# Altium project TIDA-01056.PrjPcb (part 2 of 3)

## Sheet OPA625 ADC Driver_Power_1050.SchDoc
size 558 x 431 mm; Date: Not shown in title block; ApprovedBy: Not shown in title block; CheckedBy: Not shown in title block; Author: Not shown in title block; CompanyName: Not shown in title block; Engineer: Not shown in title block; Organization: Not shown in title block; Address1: Not shown in title block; Address2: Not shown in title block; Address3: Not shown in title block; Address4: Not shown in title block; DocumentNumber: 2; Revision: Use project parameter SCH_Rev; SheetNumber: 2; SheetTotal: 8; PageSetup: Record=PageOptions¦CenterHorizontal=True¦CenterVertical=True¦PrintScale=1.00¦XCorrection=1.00¦YCorrection=1.00¦PrintKind=0¦BorderSize=5000000¦LeftOffset=0¦BottomOffset=0¦Orientation=2¦PaperLength=1000¦PaperWidth=1000¦Scale=100¦PaperSource=15¦PrintQuality=600¦MediaType=1¦DitherType=10¦PaperKind=Letter¦PrintScaleMode=1

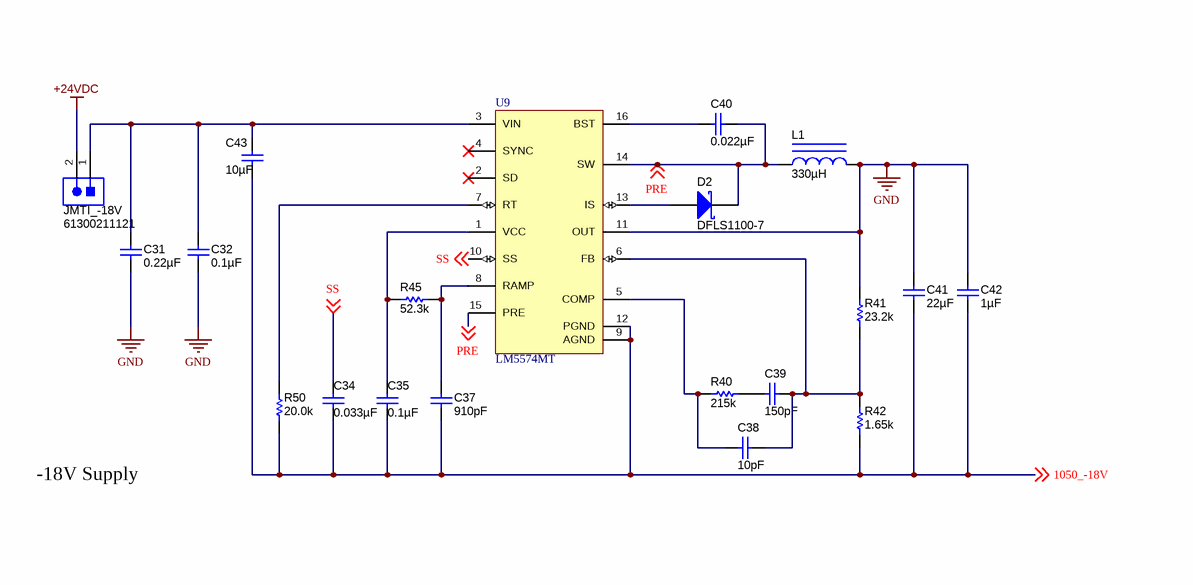
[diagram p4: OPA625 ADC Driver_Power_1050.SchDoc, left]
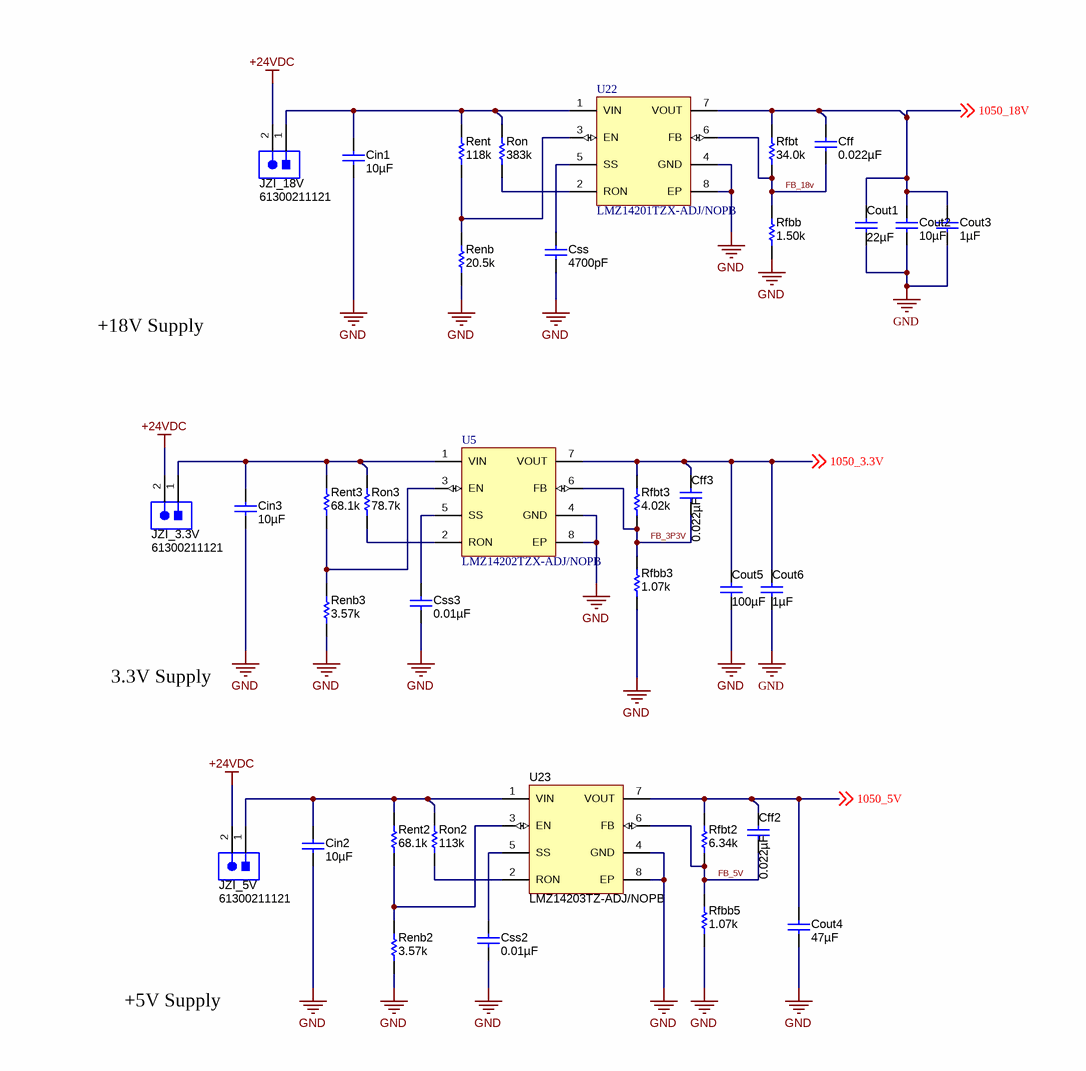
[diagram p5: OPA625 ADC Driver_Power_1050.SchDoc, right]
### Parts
C31  ValueDisplayed: 0.22µF  [0603]  (hidden comment: GCM188R71H224KA64D)
C32  ValueDisplayed: 0.1µF  [0603]  (hidden comment: C1608X7R1H104K080AA)
C34  ValueDisplayed: 0.033µF  [0603]  (hidden comment: GRM188R71H333KA61D)
C35  ValueDisplayed: 0.1µF  [0603]  (hidden comment: C1608X7R1H104K080AA)
C37  ValueDisplayed: 910pF  [0603]  (hidden comment: C0603C911J5GACTU)
C38  ValueDisplayed: 10pF  [0603]  (hidden comment: CGA3E2C0G1H100D080AA)
C39  ValueDisplayed: 150pF  [0603]  (hidden comment: GRM1885C1H151JA01D)
C40  ValueDisplayed: 0.022µF  [0603]  (hidden comment: GRM188R71H223KA01D)
C41  ValueDisplayed: 22µF  [0805_HV]  (hidden comment: C2012X5R1V226M125AC)
C42  ValueDisplayed: 1µF  [0805_HV]  (hidden comment: C2012X7S2A105K125AB)
C43  ValueDisplayed: 10µF  [1210_280]  (hidden comment: UMK325AB7106KM-T)
Cff  ValueDisplayed: 0.022µF  [0603]  (hidden comment: C1608X7R2A223K080AA)
Cff2  ValueDisplayed: 0.022µF  [0805_HV]  (hidden comment: 08055C223KAT2A)
Cff3  ValueDisplayed: 0.022µF  [0805_HV]  (hidden comment: 08055C223KAT2A)
Cin1  ValueDisplayed: 10µF  [1210_280]  (hidden comment: UMK325AB7106KM-T)
Cin2  ValueDisplayed: 10µF  [1210_280]  (hidden comment: UMK325AB7106KM-T)
Cin3  ValueDisplayed: 10µF  [1210_280]  (hidden comment: UMK325AB7106KM-T)
Cout1  ValueDisplayed: 22µF  [0805_HV]  (hidden comment: C2012JB1V226M125AC)
Cout2  ValueDisplayed: 10µF  [1210_280]  (hidden comment: UMK325AB7106KM-T)
Cout3  ValueDisplayed: 1µF  [0805_HV]  (hidden comment: C2012X7S2A105K125AB)
Cout4  ValueDisplayed: 47µF  [1206_190]  (hidden comment: C3216X5R1E476M160AC)
Cout5  ValueDisplayed: 100µF  [1210_280]  (hidden comment: C3225X6S0J107M250AC)
Cout6  ValueDisplayed: 1µF  [0603]  (hidden comment: C0603C105K3RACTU)
Css  ValueDisplayed: 4700pF  [0603]  (hidden comment: CGA3E2X7R2A472K080AA)
Css2  ValueDisplayed: 0.01µF  [0603]  (hidden comment: GRM188R70J103KA01D)
Css3  ValueDisplayed: 0.01µF  [0603]  (hidden comment: GRM188R70J103KA01D)
D2  DFLS1100-7  [PowerDI123]
JMTI_-18V  61300211121  [WURTH_61300211121]
JZI_3.3V  61300211121  [WURTH_61300211121]
JZI_5V  61300211121  [WURTH_61300211121]
JZI_18V  61300211121  [WURTH_61300211121]
L1  ValueDisplayed: 330µH  [DR73]  (hidden comment: DR73-331-R)
R40  ValueDisplayed: 215k  [0603]  (hidden comment: RT0603BRD07215KL)
R41  ValueDisplayed: 23.2k  [0603]  (hidden comment: RG1608P-2322-B-T5)
R42  ValueDisplayed: 1.65k  [0603]  (hidden comment: RG1608P-1651-B-T5)
R45  ValueDisplayed: 52.3k  [0603]  (hidden comment: RT0603BRD0752K3L)
R50  ValueDisplayed: 20.0k  [0603]  (hidden comment: RG1608P-203-B-T5)
Renb  ValueDisplayed: 20.5k  [0805_HV]  (hidden comment: CRCW080520K5FKEA)
Renb2  ValueDisplayed: 3.57k  [0603]  (hidden comment: RG1608P-3571-B-T5)
Renb3  ValueDisplayed: 3.57k  [0603]  (hidden comment: RG1608P-3571-B-T5)
Rent  value 118k  [0805_HV]  (hidden comment: RT0805BRD07118KL)
Rent2  ValueDisplayed: 68.1k  [0603]  (hidden comment: RT0603BRD0768K1L)
Rent3  ValueDisplayed: 68.1k  [0603]  (hidden comment: RT0603BRD0768K1L)
Rfbb  ValueDisplayed: 1.50k  [0603]  (hidden comment: RG1608P-152-B-T5)
Rfbb3  ValueDisplayed: 1.07k  [0805_HV]  (hidden comment: RT0805BRD071K07L)
Rfbb5  ValueDisplayed: 1.07k  [0805_HV]  (hidden comment: RT0805BRD071K07L)
Rfbt  ValueDisplayed: 34.0k  [0603]  (hidden comment: RT0603BRD0734KL)
Rfbt2  ValueDisplayed: 6.34k  [0603]  (hidden comment: CPF0603B6K34E)
Rfbt3  ValueDisplayed: 4.02k  [0603]  (hidden comment: RG1608P-4021-B-T5)
Ron  ValueDisplayed: 383k  [0603]  (hidden comment: RT0603BRD07383KL)
Ron2  ValueDisplayed: 113k  [0603]  (hidden comment: RT0603BRD07113KL)
Ron3  ValueDisplayed: 78.7k  [0603]  (hidden comment: RT0603BRD0778K7L)
U5  LMZ14202TZX-ADJ/NOPB  [TZA07A_V]
U9  LM5574MT  [MTC16_N]
U22  LMZ14201TZX-ADJ/NOPB  [TZA07A_V]
U23  LMZ14203TZ-ADJ/NOPB  [TZA07A_V]

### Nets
+24VDC: JMTI_-18V.2 JZI_3.3V.2 JZI_5V.2 JZI_18V.2
GND: C31.2 C32.2 C41.1 C42.1 Cin1.2 Cin2.2 Cin3.2 Cout1.2 Cout2.2 Cout3.2 Cout4.2 Cout5.2 Cout6.2 Css.1 Css2.2 Css3.2 L1.2 R41.2 Renb.1 Renb2.1 Renb3.1 Rfbb.1 Rfbb3.1 Rfbb5.1 U5.4(GND) U5.8(EP) U9.11(OUT) U22.4(GND) U22.8(EP) U23.4(GND) U23.8(EP)
1050_3.3V: Cff3.1 Cout5.1 Cout6.1 Rfbt3.2 U5.7(VOUT) ; off-sheet 1050_3.3V
1050_5V: Cff2.1 Cout4.1 Rfbt2.2 U23.7(VOUT) ; off-sheet 1050_5V
1050_18V: Cff.1 Cout1.1 Cout2.1 Cout3.1 Rfbt.2 U22.7(VOUT) ; off-sheet 1050_18V
1050_-18V: C34.2 C35.2 C37.2 C41.2 C42.2 C43.2 R42.1 R50.1 U9.9(AGND) U9.12(PGND) ; off-sheet 1050_-18V
FB_3P3V: Cff3.2 Rfbb3.2 Rfbt3.1 U5.6(FB)
FB_5V: Cff2.2 Rfbb5.2 Rfbt2.1 U23.6(FB)
FB_18v: Cff.2 Rfbb.2 Rfbt.1 U22.6(FB)
PRE: C40.1 D2.1(K) L1.1 U9.14(SW) U9.15(PRE) ; off-sheet PRE
SS: C34.1 U9.10(SS) ; off-sheet SS
NetC31_1: C31.1 C32.1 C43.1 JMTI_-18V.1 U9.3(VIN)
NetC35_1: C35.1 R45.1 U9.1(VCC)
NetC37_1: C37.1 R45.2 U9.8(RAMP)
NetC38_1: C38.1 C39.1 R41.1 R42.2 U9.6(FB)
NetC38_2: C38.2 R40.1 U9.5(COMP)
NetC39_2: C39.2 R40.2
NetC40_2: C40.2 U9.16(BST)
NetCin1_1: Cin1.1 JZI_18V.1 Rent.2 Ron.2 U22.1(VIN)
NetCin2_1: Cin2.1 JZI_5V.1 Rent2.2 Ron2.2 U23.1(VIN)
NetCin3_1: Cin3.1 JZI_3.3V.1 Rent3.2 Ron3.2 U5.1(VIN)
NetCss2_1: Css2.1 U23.5(SS)
NetCss3_1: Css3.1 U5.5(SS)
NetCss_2: Css.2 U22.5(SS)
NetD2_2: D2.2(A) U9.13(IS)
NetR50_2: R50.2 U9.7(RT)
NetRenb2_2: Renb2.2 Rent2.1 U23.3(EN)
NetRenb3_2: Renb3.2 Rent3.1 U5.3(EN)
NetRenb_2: Renb.2 Rent.1 U22.3(EN)
NetRon2_1: Ron2.1 U23.2(RON)
NetRon3_1: Ron3.1 U5.2(RON)
NetRon_1: Ron.1 U22.2(RON)

Not connected (* = marked no-connect by the designer): U9 2(SD)* 4(SYNC)*

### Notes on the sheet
- +18V Supply
- -18V Supply
- 3.3V Supply
- +5V Supply

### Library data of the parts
C31 = GCM188R71H224KA64D: CAP, CERM, 0.22 µF, 50 V, +/- 10%, X7R, AEC-Q200 Grade 1, 0603; Manufacturer: MuRata; Polarized: N; CompType: Capacitor; Value: 0.22uF; U/M: EA; Cap_F: 0.00000022; Tolerance_%: 10; Value1: Unknown; VDC_V: 50; Value2: 50V; TaMin_C: -55; TaMax_C: 125; SizeArea_mm2: 1.28; SizeAreaWB_mm2: 4.68; SizeX_mm: 1.6; SizeY_mm: 0.8; SizeZ_mm: 1; AEC Category: Q200; AEC Qualified: Y
C32 C35 = C1608X7R1H104K080AA: CAP, CERM, 0.1 µF, 50 V, +/- 10%, X7R, 0603; Manufacturer: TDK; Polarized: N; CompType: Capacitor; Value: 0.1uF; U/M: EA; Cap_F: 0.0000001; Tolerance_%: 10; ESR_ohm: 0.0296; Value1: 0.0296 ohm; VDC_V: 50; Value2: 50V; IRMS_A: 0.97199; TaMin_C: -55; TaMax_C: 125; SizeArea_mm2: 1.28; SizeAreaWB_mm2: 4.68; SizeX_mm: 1.6; SizeY_mm: 0.8; SizeZ_mm: 1; AEC Category: Q200
C34 = GRM188R71H333KA61D: CAP, CERM, 0.033 µF, 50 V, +/- 10%, X7R, 0603; Manufacturer: MuRata; Polarized: N; CompType: Capacitor; Value: 0.033uF; U/M: EA; Cap_F: 0.000000033; Tolerance_%: 10; Value1: Unknown; VDC_V: 50; Value2: 50V; TaMin_C: -55; TaMax_C: 125; SizeArea_mm2: 1.28; SizeAreaWB_mm2: 4.68; SizeX_mm: 1.6; SizeY_mm: 0.8; SizeZ_mm: 1; AEC Category: Q200
C37 = C0603C911J5GACTU: CAP, CERM, 910 pF, 50 V, +/- 5%, C0G/NP0, 0603; Manufacturer: Kemet; Polarized: N; CompType: Capacitor; Value: 910pF; U/M: EA; Cap_F: 0.00000000091; Tolerance_%: 5; Value1: Unknown; VDC_V: 50; Value2: 50V; TaMin_C: -55; TaMax_C: 125; SizeArea_mm2: 1.28; SizeAreaWB_mm2: 4.68; SizeX_mm: 1.6; SizeY_mm: 0.8; SizeZ_mm: 1; AEC Category: Q200
C38 = CGA3E2C0G1H100D080AA: CAP, CERM, 10 pF, 50 V, +/- 5%, C0G/NP0, AEC-Q200 Grade 1, 0603; Manufacturer: TDK; Polarized: N; CompType: Capacitor; Value: 10pF; U/M: EA; Cap_F: 0.00000000001; Tolerance_%: 5; Value1: Unknown; VDC_V: 50; Value2: 50V; TaMin_C: -55; TaMax_C: 125; SizeArea_mm2: 1.28; SizeAreaWB_mm2: 4.68; SizeX_mm: 1.6; SizeY_mm: 0.8; SizeZ_mm: 1; AEC Category: Q200; AEC Qualified: Y
C39 = GRM1885C1H151JA01D: CAP, CERM, 150 pF, 50 V, +/- 5%, C0G/NP0, 0603; Manufacturer: MuRata; Polarized: N; CompType: Capacitor; Value: 150pF; U/M: EA; Cap_F: 0.00000000015; Tolerance_%: 5; Value1: Unknown; VDC_V: 50; Value2: 50V; TaMin_C: -55; TaMax_C: 125; SizeArea_mm2: 1.28; SizeAreaWB_mm2: 4.68; SizeX_mm: 1.6; SizeY_mm: 0.8; SizeZ_mm: 1; AEC Category: Q200
C40 = GRM188R71H223KA01D: CAP, CERM, 0.022 µF, 50 V, +/- 10%, X7R, 0603; Manufacturer: MuRata; Polarized: N; CompType: Capacitor; Value: 0.022uF; U/M: EA; Cap_F: 0.000000022; Tolerance_%: 10; Value1: Unknown; VDC_V: 50; Value2: 50V; TaMin_C: -55; TaMax_C: 125; SizeArea_mm2: 1.28; SizeAreaWB_mm2: 4.68; SizeX_mm: 1.6; SizeY_mm: 0.8; SizeZ_mm: 1; AEC Category: Q200
C41 = C2012X5R1V226M125AC: CAP, CERM, 22 µF, 35 V, +/- 20%, X5R, 0805; Manufacturer: TDK; Polarized: N; CompType: Capacitor; Value: 22uF; U/M: EA; Cap_F: 0.000022; Tolerance_%: 20; ESR_ohm: 0.00205; Value1: 0.00205 ohm; VDC_V: 35; Value2: 35V; IRMS_A: 4.55587; TaMin_C: -55; TaMax_C: 85; Cap_Case: 0805; SizeArea_mm2: 2.5; SizeAreaWB_mm2: 6.75; SizeX_mm: 2; SizeY_mm: 1.25; SizeZ_mm: 1.45; AEC Category: Q200
C42 Cout3 = C2012X7S2A105K125AB: CAP, CERM, 1 µF, 100 V, +/- 10%, X7S, 0805; Manufacturer: TDK; Polarized: N; CompType: Capacitor; Value: 1uF; U/M: EA; Cap_F: 0.000001; Tolerance_%: 10; ESR_ohm: 0.008255; Value1: 0.008255 ohm; VDC_V: 100; Value2: 100V; IRMS_A: 2.27442; TaMin_C: -55; TaMax_C: 125; Cap_Case: 0805; SizeArea_mm2: 2.5; SizeAreaWB_mm2: 6.75; SizeX_mm: 2; SizeY_mm: 1.25; SizeZ_mm: 1.45; AEC Category: Q200
C43 = UMK325AB7106KM-T: CAP, CERM, 10 µF, 50 V, +/- 10%, X7R, 1210; Manufacturer: Taiyo Yuden; Polarized: N; CompType: Capacitor; Value: 10uF; U/M: EA; Cap_F: 0.00001; Tolerance_%: 10; Value1: Unknown; VDC_V: 50; Value2: 50V; TaMin_C: -55; TaMax_C: 125; Cap_Case: 1210; AEC Category: Q200
Cff = C1608X7R2A223K080AA: CAP, CERM, 0.022 µF, 100 V, +/- 10%, X7R, 0603; Manufacturer: TDK; Polarized: N; CompType: Capacitor; Value: 0.022uF; U/M: EA; Cap_F: 0.000000022; Tolerance_%: 10; ESR_ohm: 0.037; Value1: 0.037 ohm; VDC_V: 100; Value2: 100V; TaMin_C: -55; TaMax_C: 125; SizeArea_mm2: 1.28; SizeAreaWB_mm2: 4.68; SizeX_mm: 1.6; SizeY_mm: 0.8; SizeZ_mm: 1; AEC Category: Q200
Cff2 Cff3 = 08055C223KAT2A: CAP, CERM, 0.022uF, 50V, +/-10%, X7R, 0805; Manufacturer: AVX; Polarized: N; CompType: Capacitor; U/M: EA; Cap_F: 0.000000022; Tolerance_%: 10; ESR_Ohm: 0.052; Value1: 0.052 ohm; VDC_V: 50; TaMin_C: -55; TaMax_C: 125; Cap_Case: 0805
Cin1-Cin3 Cout2 = UMK325AB7106KM-T: CAP, CERM, 10 µF, 50 V, +/- 10%, X7R, 1210; Manufacturer: Taiyo Yuden; Polarized: N; CompType: Capacitor; Value: 10uF; U/M: EA; Cap_F: 0.00001; Tolerance_%: 10; Value1: Unknown; VDC_V: 50; Value2: 50V; TaMin_C: -55; TaMax_C: 125; Cap_Case: 1210; SizeArea_mm2: 8; SizeAreaWB_mm2: 14.7; SizeX_mm: 3.2; SizeY_mm: 2.5; SizeZ_mm: 2.8; AEC Category: Q200
Cout1 = C2012JB1V226M125AC: CAP, CERM, 22 µF, 35 V, +/- 20%, JB, 0805; Manufacturer: TDK; Polarized: N; CompType: Capacitor; Value: 22uF; U/M: EA; Cap_F: 0.000022; Tolerance_%: 20; Value1: Unknown; VDC_V: 35; Value2: 35V; TaMin_C: -25; TaMax_C: 85; Cap_Case: 0805; SizeArea_mm2: 2.5; SizeAreaWB_mm2: 6.75; SizeX_mm: 2; SizeY_mm: 1.25; SizeZ_mm: 1.45; AEC Category: Q200
Cout4 = C3216X5R1E476M160AC: CAP, CERM, 47 µF, 25 V, +/- 20%, X5R, 1206_190; Manufacturer: TDK; Polarized: N; CompType: Capacitor; Value: 47uF; U/M: EA; Cap_F: 0.000047; Tolerance_%: 20; Value1: Unknown; VDC_V: 25; Value2: 25V; TaMin_C: -55; TaMax_C: 85; Cap_Case: 1206; AEC Category: Q200
Cout5 = C3225X6S0J107M250AC: CAP, CERM, 100 µF, 6.3 V, +/- 20%, X6S, 1210; Manufacturer: TDK; Polarized: N; CompType: Capacitor; Value: 100uF; U/M: EA; Cap_F: 0.0001; Tolerance_%: 20; ESR_ohm: 0.005496; Value1: 0.005496 ohm; VDC_V: 6.3; Value2: 6.3V; IRMS_A: 3.13651; TaMin_C: -55; TaMax_C: 105; SizeArea_mm2: 8; SizeAreaWB_mm2: 14.7; SizeX_mm: 3.2; SizeY_mm: 2.5; SizeZ_mm: 2.8; AEC Category: Q200
Cout6 = C0603C105K3RACTU: CAP, CERM, 1 µF, 25 V, +/- 10%, X7R, 0603; Manufacturer: Kemet; Polarized: N; CompType: Capacitor; Value: 1uF; U/M: EA; Cap_F: 0.000001; Tolerance_%: 10; Value1: Unknown; VDC_V: 25; Value2: 25V; TaMin_C: -55; TaMax_C: 125; SizeArea_mm2: 1.28; SizeAreaWB_mm2: 4.68; SizeX_mm: 1.6; SizeY_mm: 0.8; SizeZ_mm: 1; AEC Category: Q200
Css = CGA3E2X7R2A472K080AA: CAP, CERM, 4700 pF, 100 V, +/- 10%, X7R, AEC-Q200 Grade 1, 0603; Manufacturer: TDK; Polarized: N; CompType: Capacitor; Value: 4700pF; U/M: EA; Cap_F: 0.0000000047; Tolerance_%: 10; ESR_ohm: 0.469862; Value1: 0.469862 ohm; VDC_V: 100; Value2: 100V; IRMS_A: 0.32335; TaMin_C: -55; TaMax_C: 125; SizeArea_mm2: 1.28; SizeAreaWB_mm2: 4.68; SizeX_mm: 1.6; SizeY_mm: 0.8; SizeZ_mm: 1; AEC Category: Q200; AEC Qualified: Y
Css2 Css3 = GRM188R70J103KA01D: CAP, CERM, 0.01 µF, 6.3 V, +/- 10%, X7R, 0603; Manufacturer: MuRata; Polarized: N; CompType: Capacitor; Value: 0.01uF; U/M: EA; Cap_F: 0.00000001; Tolerance_%: 10; Value1: Unknown; VDC_V: 6.3; Value2: 6.3V; TaMin_C: -55; TaMax_C: 125; SizeArea_mm2: 1.28; SizeAreaWB_mm2: 4.68; SizeX_mm: 1.6; SizeY_mm: 0.8; SizeZ_mm: 1; AEC Category: Q200
D2 = DFLS1100-7: Diode, Schottky, 100 V, 1 A, PowerDI123; Manufacturer: Diodes Inc.; U/M: EA; Vf_V: 0.77; Value: 100V; Value1: 1A; Value2: 0.77V; Io_A: 1; Vr_V: 100; TJmax_C: 175; RJC_CperW: 7; SizeAreaWB_mm2: 13.066; SizeArea_mm2: 6.586; SizeX_mm: 3.7; SizeY_mm: 1.78; SizeZ_mm: 0.98; AEC Category: Q101
JMTI_-18V JZI_3.3V JZI_5V JZI_18V = 61300211121: Header, 2.54 mm, 2x1, Gold, TH; Manufacturer: Wurth Elektronik; SymbolCreator: a0412235
L1 = DR73-331-R: Inductor, Shielded Drum Core, Ferrite, 330 µH, 0.42 A, 1.59 ohm, SMD; Manufacturer: Coiltronics; Value: 330uH; Ind_H: 330.0E-6; Imax_A: 0.42; Irms: 0.42A @ 40C rise; Isat: 0.44A @ 30% inductance drop; DCR_ohm: 1.59; Value2: 0.42A; AEC Category: Q200
R40 = RT0603BRD07215KL: RES, 215 k, 0.1%, 0.1 W, 0603; Manufacturer: Yageo America; CompType: Resistor; Value: 215k; Res_ohm: 215000; Tolerance_%: 0.1; Value2: 0.1W; VDC_V: 75; TempCo: 25 ppm/C; SizeArea_mm2: 1.28; SizeX_mm: 1.6; SizeY_mm: 0.8; SizeZ_mm: 1; EIA_Code: E192; U/M: EA; AEC Category: Q200
R41 = RG1608P-2322-B-T5: RES, 23.2 k, 0.1%, 0.1 W, 0603; Manufacturer: Susumu Co Ltd; CompType: Resistor; Value: 23.2k; Res_ohm: 23200; Value_Code: 23k2; Tolerance_%: 0.1; Value2: 0.1W; VDC_V: 75; TempCo: 25 ppm/C; SizeArea_mm2: 1.28; SizeX_mm: 1.6; SizeY_mm: 0.8; SizeZ_mm: 1; EIA_Code: E192; U/M: EA; AEC Category: Q200
R42 = RG1608P-1651-B-T5: RES, 1.65 k, 0.1%, 0.1 W, 0603; Manufacturer: Susumu Co Ltd; CompType: Resistor; Value: 1.65k; Res_ohm: 1650; Value_Code: 1k65; Tolerance_%: 0.1; Value2: 0.1W; VDC_V: 75; TempCo: 25 ppm/C; SizeArea_mm2: 1.28; SizeX_mm: 1.6; SizeY_mm: 0.8; SizeZ_mm: 1; EIA_Code: E192; U/M: EA; AEC Category: Q200
R45 = RT0603BRD0752K3L: RES, 52.3 k, 0.1%, 0.1 W, 0603; Manufacturer: Yageo America; CompType: Resistor; Value: 52.3k; Res_ohm: 52300; Value_Code: 52k3; Tolerance_%: 0.1; Value2: 0.1W; VDC_V: 75; TempCo: 25 ppm/C; SizeArea_mm2: 1.28; SizeX_mm: 1.6; SizeY_mm: 0.8; SizeZ_mm: 1; EIA_Code: E192; U/M: EA; AEC Category: Q200
R50 = RG1608P-203-B-T5: RES, 20.0 k, 0.1%, 0.1 W, 0603; Manufacturer: Susumu Co Ltd; CompType: Resistor; Value: 20.0k; Res_ohm: 20000; Value_Code: 20k0; Tolerance_%: 0.1; Value2: 0.1W; VDC_V: 75; TempCo: 25 ppm/C; SizeArea_mm2: 1.28; SizeX_mm: 1.6; SizeY_mm: 0.8; SizeZ_mm: 1; EIA_Code: E192; U/M: EA; AEC Category: Q200
Renb = CRCW080520K5FKEA: RES, 20.5 k, 1%, 0.125 W, 0805; Manufacturer: Vishay-Dale; CompType: Resistor; Value: 20.5k; Res_ohm: 20500; Value_Code: 20k5; Tolerance_%: 1; Power_W: 0.125; Value2: 0.125W; VDC_V: 150; TempCo: 100 ppm/C; EIA_Code: E96; U/M: EA; AEC Category: Q200
Renb2 Renb3 = RG1608P-3571-B-T5: RES, 3.57 k, 0.1%, 0.1 W, 0603; Manufacturer: Susumu Co Ltd; CompType: Resistor; Value: 3.57k; Res_ohm: 3570; Value_Code: 3k57; Tolerance_%: 0.1; Value2: 0.1W; VDC_V: 75; TempCo: 25 ppm/C; SizeArea_mm2: 1.28; SizeX_mm: 1.6; SizeY_mm: 0.8; SizeZ_mm: 1; EIA_Code: E192; U/M: EA; AEC Category: Q200
Rent = RT0805BRD07118KL: RES, 118k ohm, 0.1%, 0.125W, 0805; Manufacturer: Yageo America; CompType: Resistor; Res_ohm: 118000; Tolerance_%: 0.1; Power_W: 0.125; VDC_V: 150; TempCo: 25 ppm/C; EIA_Code: E192; U/M: EA
Rent2 Rent3 = RT0603BRD0768K1L: RES, 68.1 k, 0.1%, 0.1 W, 0603; Manufacturer: Yageo America; CompType: Resistor; Value: 68.1k; Res_ohm: 68100; Value_Code: 68k1; Tolerance_%: 0.1; Value2: 0.1W; VDC_V: 75; TempCo: 25 ppm/C; SizeArea_mm2: 1.28; SizeX_mm: 1.6; SizeY_mm: 0.8; SizeZ_mm: 1; EIA_Code: E192; U/M: EA; AEC Category: Q200
Rfbb = RG1608P-152-B-T5: RES, 1.50 k, 0.1%, 0.1 W, 0603; Manufacturer: Susumu Co Ltd; CompType: Resistor; Value: 1.50k; Res_ohm: 1500; Value_Code: 1k50; Tolerance_%: 0.1; Value2: 0.1W; VDC_V: 75; TempCo: 25 ppm/C; SizeArea_mm2: 1.28; SizeX_mm: 1.6; SizeY_mm: 0.8; SizeZ_mm: 1; EIA_Code: E192; U/M: EA; AEC Category: Q200
Rfbb3 Rfbb5 = RT0805BRD071K07L: RES, 1.07 k, 0.1%, 0.125 W, 0805; Manufacturer: Yageo America; CompType: Resistor; Value: 1.07k; Res_ohm: 1070; Value_Code: 1k07; Tolerance_%: 0.1; Power_W: 0.125; Value2: 0.125W; VDC_V: 150; TempCo: 25 ppm/C; EIA_Code: E192; U/M: EA; AEC Category: Q200
Rfbt = RT0603BRD0734KL: RES, 34.0 k, 0.1%, 0.1 W, 0603; Manufacturer: Yageo America; CompType: Resistor; Value: 34.0k; Res_ohm: 34000; Value_Code: 34k0; Tolerance_%: 0.1; Value2: 0.1W; VDC_V: 75; TempCo: 25 ppm/C; SizeArea_mm2: 1.28; SizeX_mm: 1.6; SizeY_mm: 0.8; SizeZ_mm: 1; EIA_Code: E192; U/M: EA; AEC Category: Q200
Rfbt2 = CPF0603B6K34E: RES, 6.34 k, 0.1%, 0.063 W, 0603; Manufacturer: TE Connectivity; CompType: Resistor; Value: 6.34k; Res_ohm: 6340; Value_Code: 6k34; Tolerance_%: 0.1; Power_W: 0.063; Value2: 0.063W; VDC_V: 50; TempCo: 25 ppm/C; SizeArea_mm2: 1.28; SizeX_mm: 1.6; SizeY_mm: 0.8; SizeZ_mm: 1; EIA_Code: E192; U/M: EA; AEC Category: Q200
Rfbt3 = RG1608P-4021-B-T5: RES, 4.02 k, 0.1%, 0.1 W, 0603; Manufacturer: Susumu Co Ltd; CompType: Resistor; Value: 4.02k; Res_ohm: 4020; Value_Code: 4k02; Tolerance_%: 0.1; Value2: 0.1W; VDC_V: 75; TempCo: 25 ppm/C; SizeArea_mm2: 1.28; SizeX_mm: 1.6; SizeY_mm: 0.8; SizeZ_mm: 1; EIA_Code: E192; U/M: EA; AEC Category: Q200
Ron = RT0603BRD07383KL: RES, 383 k, 0.1%, 0.1 W, 0603; Manufacturer: Yageo America; CompType: Resistor; Value: 383k; Res_ohm: 383000; Tolerance_%: 0.1; Value2: 0.1W; VDC_V: 75; TempCo: 25 ppm/C; SizeArea_mm2: 1.28; SizeX_mm: 1.6; SizeY_mm: 0.8; SizeZ_mm: 1; EIA_Code: E192; U/M: EA; AEC Category: Q200
Ron2 = RT0603BRD07113KL: RES, 113 k, 0.1%, 0.1 W, 0603; Manufacturer: Yageo America; CompType: Resistor; Value: 113k; Res_ohm: 113000; Tolerance_%: 0.1; Value2: 0.1W; VDC_V: 75; TempCo: 25 ppm/C; SizeArea_mm2: 1.28; SizeX_mm: 1.6; SizeY_mm: 0.8; SizeZ_mm: 1; EIA_Code: E192; U/M: EA; AEC Category: Q200
Ron3 = RT0603BRD0778K7L: RES, 78.7 k, 0.1%, 0.1 W, 0603; Manufacturer: Yageo America; CompType: Resistor; Value: 78.7k; Res_ohm: 78700; Value_Code: 78k7; Tolerance_%: 0.1; Value2: 0.1W; VDC_V: 75; TempCo: 25 ppm/C; SizeArea_mm2: 1.28; SizeX_mm: 1.6; SizeY_mm: 0.8; SizeZ_mm: 1; EIA_Code: E192; U/M: EA; AEC Category: Q200
U5 = LMZ14202TZX-ADJ/NOPB: 2A SIMPLE SWITCHER® Power Module with 42V Maximum Input, 7 pin TO-PMOD; Manufacturer: Texas Instruments; PackageTopMarking: NSUZXYTTE#*LMZ14202*TZ-ADJ; PowerWise: Y
U9 = LM5574MT: SIMPLE SWITCHER® 75V, 0.5A Step-Down Switching Regulator, 16-pin TSSOP; Manufacturer: Texas Instruments; PackageTopMarking: NSUZXYTT*LM5574*MT; PowerWise: Y
U22 = LMZ14201TZX-ADJ/NOPB: 1A SIMPLE SWITCHER® Power Module with 42V Maximum Input, 7 pin TO-PMOD; Manufacturer: Texas Instruments; PackageTopMarking: NSUZXYTTE#*LMZ14201*TZ-ADJ; PowerWise: Y
U23 = LMZ14203TZ-ADJ/NOPB: 3A SIMPLE SWITCHER® Power Module with 42V Maximum Input Voltage, 7-pin TO-PMOD, Pb-Free; Manufacturer: Texas Instruments; PackageTopMarking: NSUZXYTTE#*LMZ14203*TZ-ADJ; PowerWise: Y

## Sheet OPA625 ADC Driver_CoverSheet.SchDoc
size 431 x 279 mm; Date: Not shown in title block; ApprovedBy: Not shown in title block; CheckedBy: Not shown in title block; Author: Not shown in title block; CompanyName: Not shown in title block; Engineer: Not shown in title block; Organization: Not shown in title block; Address1: Not shown in title block; Address2: Not shown in title block; Address3: Not shown in title block; Address4: Not shown in title block; DocumentNumber: 1; Revision: Use project parameter SCH_Rev; SheetNumber: 1; SheetTotal: 8; PageSetup: Record=PageOptions¦CenterHorizontal=True¦CenterVertical=True¦PrintScale=1.00¦XCorrection=1.00¦YCorrection=1.00¦PrintKind=0¦BorderSize=5000000¦LeftOffset=0¦BottomOffset=0¦Orientation=2¦PaperLength=1000¦PaperWidth=1000¦Scale=100¦PaperSource=15¦PrintQuality=600¦MediaType=1¦DitherType=10¦PaperKind=Letter¦PrintScaleMode=1

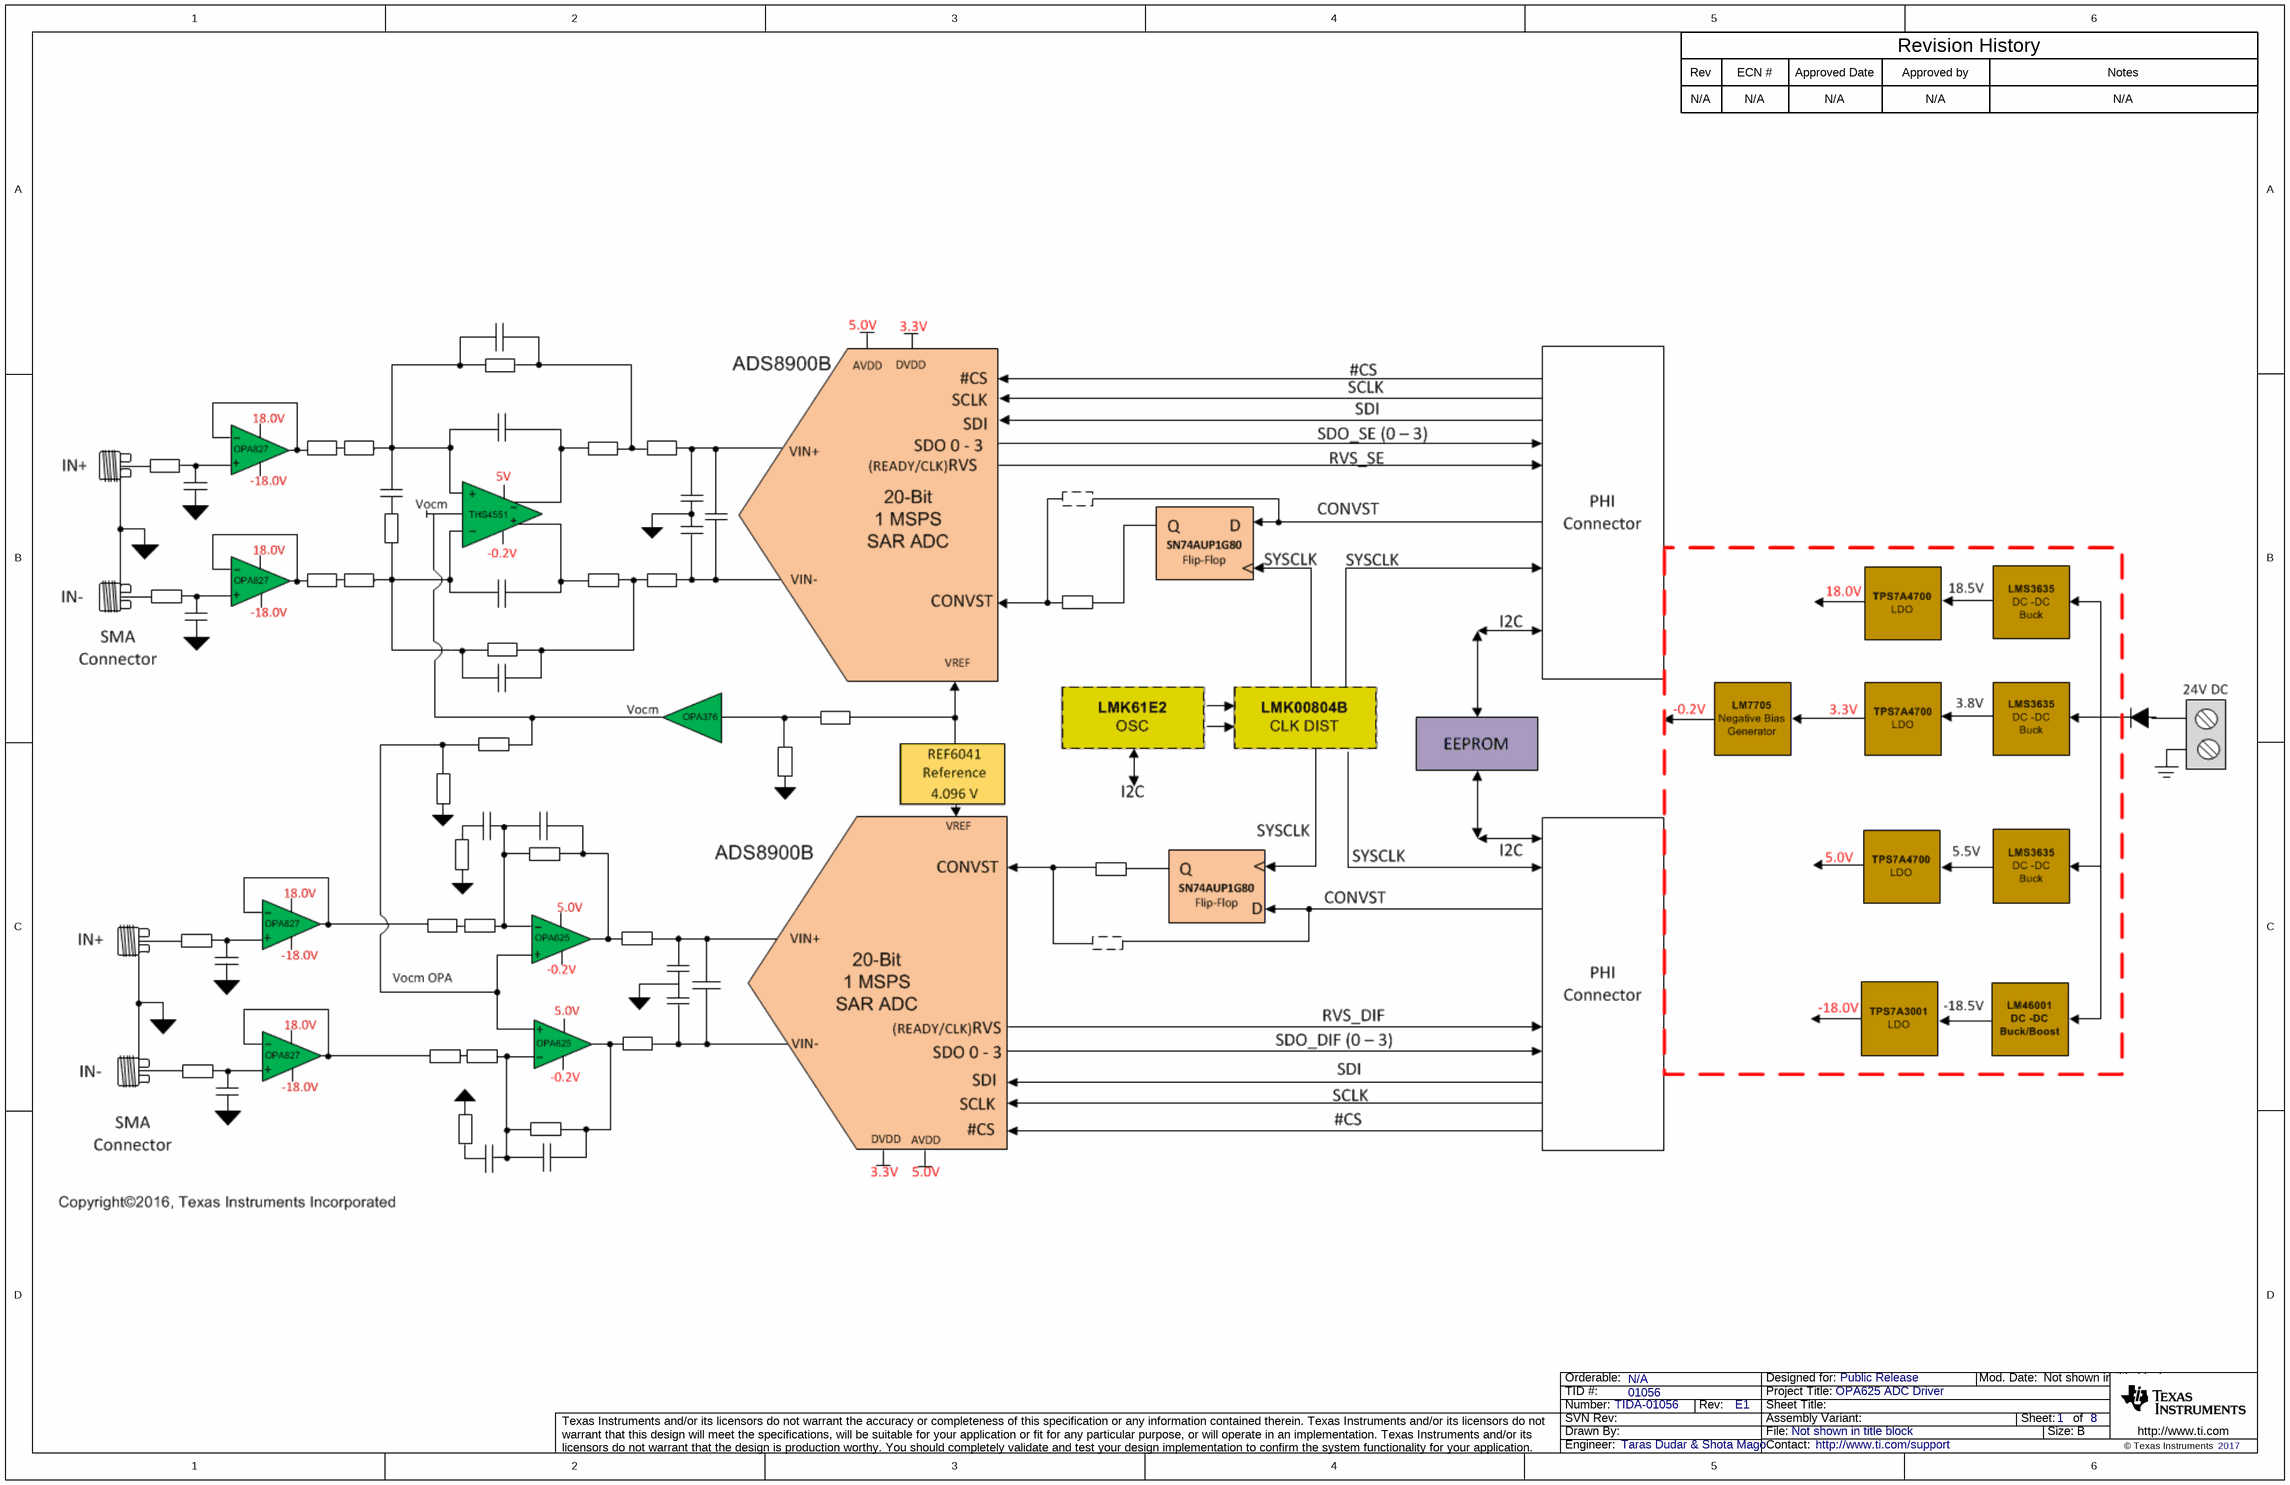
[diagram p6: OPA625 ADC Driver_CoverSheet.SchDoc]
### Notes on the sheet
- Rev
- N/A
- ECN #
- Approved Date
- Approved by
- Revision History
- Notes

## Sheet OPA625 ADC Driver_Connectors.SchDoc
size 431 x 279 mm; Date: Not shown in title block; ApprovedBy: Not shown in title block; CheckedBy: Not shown in title block; Author: Not shown in title block; CompanyName: Not shown in title block; Engineer: Not shown in title block; Organization: Not shown in title block; Address1: Not shown in title block; Address2: Not shown in title block; Address3: Not shown in title block; Address4: Not shown in title block; DocumentNumber: 3; Revision: Use project parameter SCH_Rev; SheetNumber: 3; SheetTotal: 8; PageSetup: Record=PageOptions¦CenterHorizontal=True¦CenterVertical=True¦PrintScale=0.96¦XCorrection=1.00¦YCorrection=1.00¦PrintKind=0¦BorderSize=5000000¦LeftOffset=0¦BottomOffset=0¦Orientation=2¦PaperLength=1000¦PaperWidth=1000¦Scale=100¦PaperSource=15¦PrintQuality=-3¦MediaType=1¦DitherType=10¦PrintScaleMode=1¦PaperKind=Tabloid (11 x 17")¦PaperIndex=17

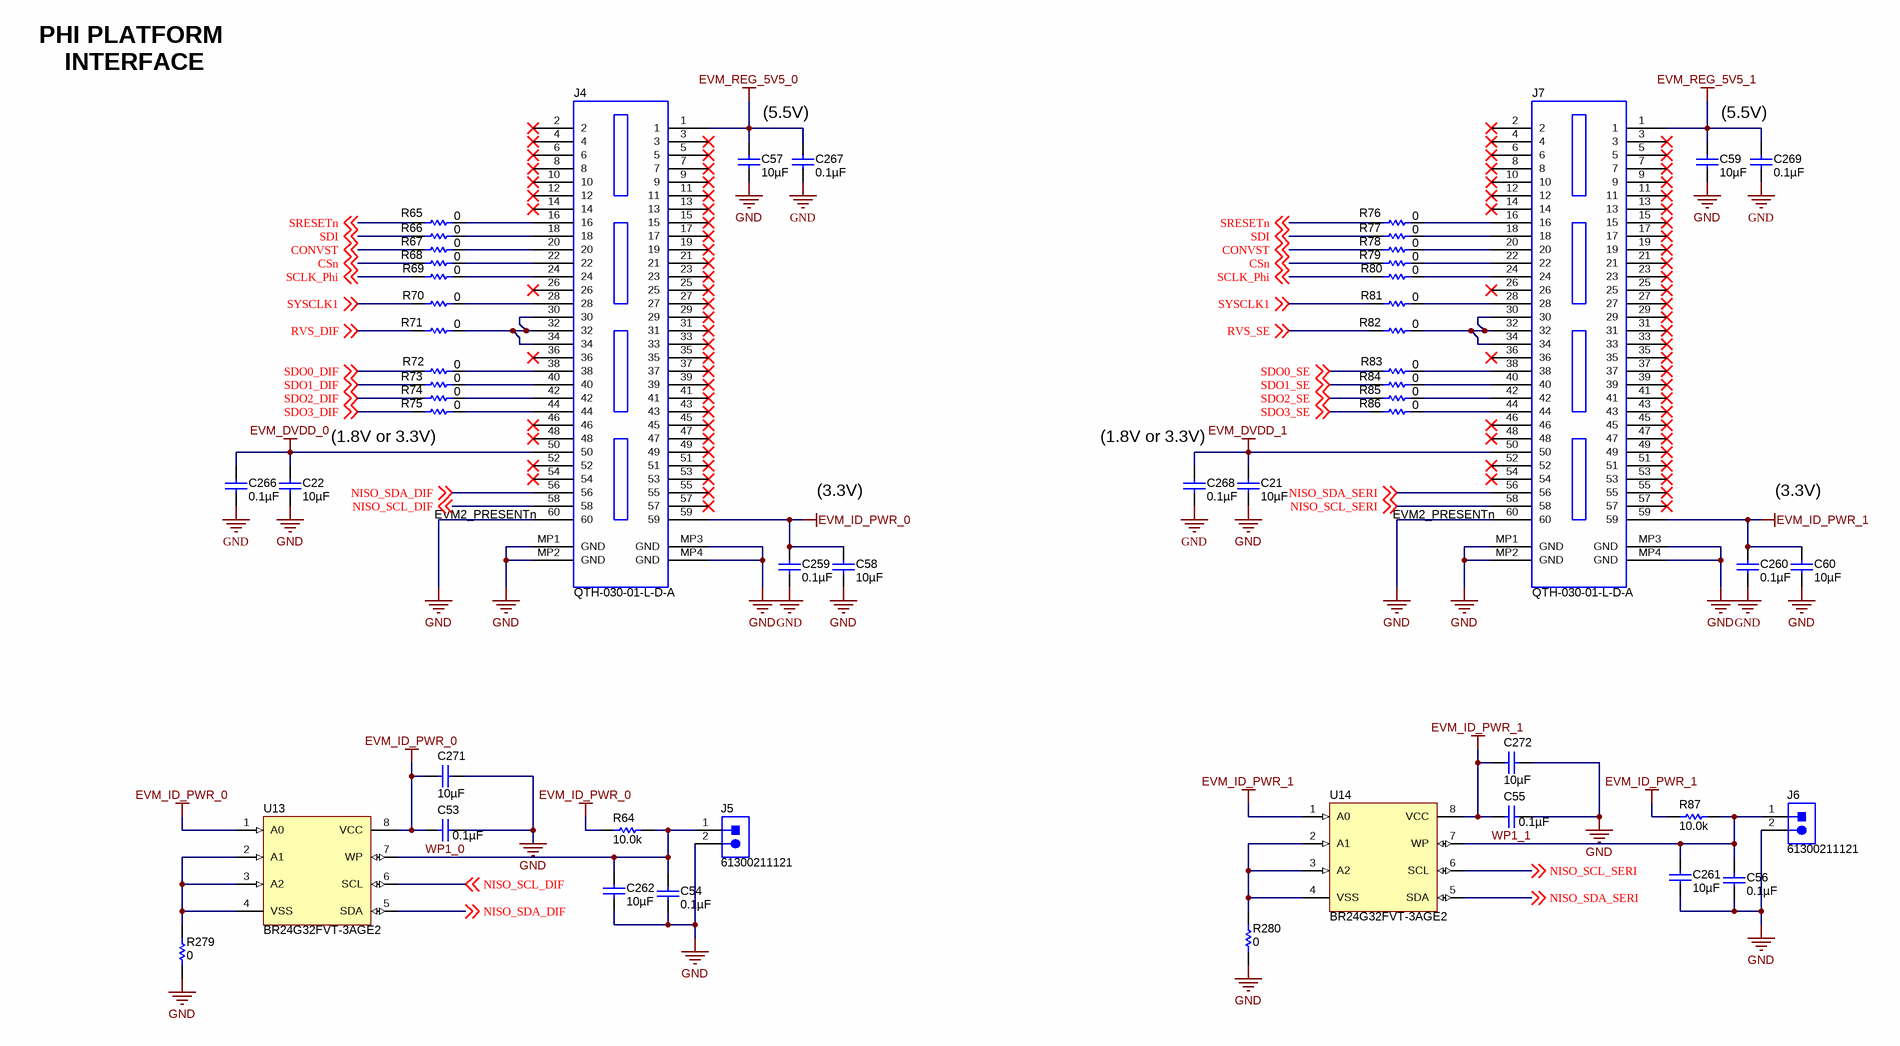
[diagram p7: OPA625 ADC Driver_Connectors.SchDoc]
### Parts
C21  ValueDisplayed: 10µF  [0805_HV]  (hidden comment: GRM21BR71A106KE51L)
C22  ValueDisplayed: 10µF  [0805_HV]  (hidden comment: GRM21BR71A106KE51L)
C53  ValueDisplayed: 0.1µF  [0402]  (hidden comment: GRM155R71C104KA88D)
C54  ValueDisplayed: 0.1µF  [0402]  (hidden comment: GRM155R71C104KA88D)
C55  ValueDisplayed: 0.1µF  [0402]  (hidden comment: GRM155R71C104KA88D)
C56  ValueDisplayed: 0.1µF  [0402]  (hidden comment: GRM155R71C104KA88D)
C57  ValueDisplayed: 10µF  [0805_HV]  (hidden comment: GRM21BR71A106KE51L)
C58  ValueDisplayed: 10µF  [0805_HV]  (hidden comment: GRM21BR71A106KE51L)
C59  ValueDisplayed: 10µF  [0805_HV]  (hidden comment: GRM21BR71A106KE51L)
C60  ValueDisplayed: 10µF  [0805_HV]  (hidden comment: GRM21BR71A106KE51L)
C259  ValueDisplayed: 0.1µF  [0603]  (hidden comment: C0603C104J3RACTU)
C260  ValueDisplayed: 0.1µF  [0603]  (hidden comment: C0603C104J3RACTU)
C261  ValueDisplayed: 10µF  [0805_HV]  (hidden comment: GRM21BR71A106KE51L)
C262  ValueDisplayed: 10µF  [0805_HV]  (hidden comment: GRM21BR71A106KE51L)
C266  ValueDisplayed: 0.1µF  [0603]  (hidden comment: C0603C104J3RACTU)
C267  ValueDisplayed: 0.1µF  [0603]  (hidden comment: C0603C104J3RACTU)
C268  ValueDisplayed: 0.1µF  [0603]  (hidden comment: C0603C104J3RACTU)
C269  ValueDisplayed: 0.1µF  [0603]  (hidden comment: C0603C104J3RACTU)
C271  ValueDisplayed: 10µF  [0805_HV]  (hidden comment: GRM21BR71A106KE51L)
C272  ValueDisplayed: 10µF  [0805_HV]  (hidden comment: GRM21BR71A106KE51L)
J4  QTH-030-01-L-D-A  [Samtec_QTH-030-01-x-D-A]
J5  61300211121  [WURTH_61300211121]
J6  61300211121  [WURTH_61300211121]
J7  QTH-030-01-L-D-A  [Samtec_QTH-030-01-x-D-A]
R64  ValueDisplayed: 10.0k  [0603]  (hidden comment: CRCW060310K0FKEA)
R65  ValueDisplayed: 0  [0402]  (hidden comment: ERJ-2GE0R00X)
R66  ValueDisplayed: 0  [0402]  (hidden comment: ERJ-2GE0R00X)
R67  ValueDisplayed: 0  [0402]  (hidden comment: ERJ-2GE0R00X)
R68  ValueDisplayed: 0  [0402]  (hidden comment: ERJ-2GE0R00X)
R69  ValueDisplayed: 0  [0402]  (hidden comment: ERJ-2GE0R00X)
R70  ValueDisplayed: 0  [0402]  (hidden comment: ERJ-2GE0R00X)
R71  ValueDisplayed: 0  [0402]  (hidden comment: ERJ-2GE0R00X)
R72  ValueDisplayed: 0  [0402]  (hidden comment: ERJ-2GE0R00X)
R73  ValueDisplayed: 0  [0402]  (hidden comment: ERJ-2GE0R00X)
R74  ValueDisplayed: 0  [0402]  (hidden comment: ERJ-2GE0R00X)
R75  ValueDisplayed: 0  [0402]  (hidden comment: ERJ-2GE0R00X)
R76  ValueDisplayed: 0  [0402]  (hidden comment: ERJ-2GE0R00X)
R77  ValueDisplayed: 0  [0402]  (hidden comment: ERJ-2GE0R00X)
R78  ValueDisplayed: 0  [0402]  (hidden comment: ERJ-2GE0R00X)
R79  ValueDisplayed: 0  [0402]  (hidden comment: ERJ-2GE0R00X)
R80  ValueDisplayed: 0  [0402]  (hidden comment: ERJ-2GE0R00X)
R81  ValueDisplayed: 0  [0402]  (hidden comment: ERJ-2GE0R00X)
R82  ValueDisplayed: 0  [0402]  (hidden comment: ERJ-2GE0R00X)
R83  ValueDisplayed: 0  [0402]  (hidden comment: ERJ-2GE0R00X)
R84  ValueDisplayed: 0  [0402]  (hidden comment: ERJ-2GE0R00X)
R85  ValueDisplayed: 0  [0402]  (hidden comment: ERJ-2GE0R00X)
R86  ValueDisplayed: 0  [0402]  (hidden comment: ERJ-2GE0R00X)
R87  ValueDisplayed: 10.0k  [0603]  (hidden comment: CRCW060310K0FKEA)
R279  ValueDisplayed: 0  [0402]  (hidden comment: ERJ-2GE0R00X)
R280  ValueDisplayed: 0  [0402]  (hidden comment: ERJ-2GE0R00X)
U13  BR24G32FVT-3AGE2  [TSOP65P640X120-8N]
U14  BR24G32FVT-3AGE2  [TSOP65P640X120-8N]

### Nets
EVM_DVDD_0: C22.1 C266.1 J4.50
EVM_DVDD_1: C21.1 C268.1 J7.50
EVM_ID_PWR_0: C53.2 C58.1 C259.1 C271.1 J4.59 R64.2 U13.1(A0) U13.8(VCC)
EVM_ID_PWR_1: C55.2 C60.1 C260.1 C272.1 J7.59 R87.2 U14.1(A0) U14.8(VCC)
EVM_REG_5V5_0: C57.1 C267.1 J4.1
EVM_REG_5V5_1: C59.1 C269.1 J7.1
GND: C21.2 C22.2 C53.1 C54.1 C55.1 C56.1 C57.2 C58.2 C59.2 C60.2 C259.2 C260.2 C261.2 C262.2 C266.2 C267.2 C268.2 C269.2 C271.2 C272.2 J4.60 J4.MP1(GND) J4.MP2(GND) J4.MP3(GND) J4.MP4(GND) J5.2 J6.2 J7.60 J7.MP1(GND) J7.MP2(GND) J7.MP3(GND) J7.MP4(GND) R279.1 R280.1
CONVST: R67.1 R78.1 ; off-sheet CONVST
CSn: R68.1 R79.1 ; off-sheet CSn
NISO_SCL_DIF: J4.58 U13.6(SCL) ; off-sheet NISO_SCL_DIF
NISO_SCL_SERI: J7.58 U14.6(SCL) ; off-sheet NISO_SCL_SERI
NISO_SDA_DIF: J4.56 U13.5(SDA) ; off-sheet NISO_SDA_DIF
NISO_SDA_SERI: J7.56 U14.5(SDA) ; off-sheet NISO_SDA_SERI
RVS_DIF: R71.1 ; off-sheet RVS_DIF
RVS_SE: R82.1 ; off-sheet RVS_SE
SCLK_Phi: R69.1 R80.1 ; off-sheet SCLK_Phi
SDI: R66.1 R77.1 ; off-sheet SDI
SDO0_DIF: R72.1 ; off-sheet SDO0_DIF
SDO0_SE: R83.1 ; off-sheet SDO0_SE
SDO1_DIF: R73.1 ; off-sheet SDO1_DIF
SDO1_SE: R84.1 ; off-sheet SDO1_SE
SDO2_DIF: R74.1 ; off-sheet SDO2_DIF
SDO2_SE: R85.1 ; off-sheet SDO2_SE
SDO3_DIF: R75.1 ; off-sheet SDO3_DIF
SDO3_SE: R86.1 ; off-sheet SDO3_SE
SRESETn: R65.1 R76.1 ; off-sheet SRESETn
SYSCLK1: R70.1 R81.1 ; off-sheet SYSCLK1
WP1_0: C54.2 C262.1 J5.1 R64.1 U13.7(WP)
WP1_1: C56.2 C261.1 J6.1 R87.1 U14.7(WP)
NetJ4_16: J4.16 R65.2
NetJ4_18: J4.18 R66.2
NetJ4_20: J4.20 R67.2
NetJ4_22: J4.22 R68.2
NetJ4_24: J4.24 R69.2
NetJ4_28: J4.28 R70.2
NetJ4_30: J4.30 J4.32 J4.34 R71.2
NetJ4_38: J4.38 R72.2
NetJ4_40: J4.40 R73.2
NetJ4_42: J4.42 R74.2
NetJ4_44: J4.44 R75.2
NetJ7_16: J7.16 R76.2
NetJ7_18: J7.18 R77.2
NetJ7_20: J7.20 R78.2
NetJ7_22: J7.22 R79.2
NetJ7_24: J7.24 R80.2
NetJ7_28: J7.28 R81.2
NetJ7_30: J7.30 J7.32 J7.34 R82.2
NetJ7_38: J7.38 R83.2
NetJ7_40: J7.40 R84.2
NetJ7_42: J7.42 R85.2
NetJ7_44: J7.44 R86.2
NetR279_2: R279.2 U13.2(A1) U13.3(A2) U13.4(VSS)
NetR280_2: R280.2 U14.2(A1) U14.3(A2) U14.4(VSS)

Not connected (* = marked no-connect by the designer): J4 2* 3* 4* 5* 6* 7* 8* 9* 10* 11* 12* 13* 14* 15* 17* 19* 21* 23* 25* 26* 27* 29* 31* 33* 35* 36* 37* 39* 41* 43* 45* 46* 47* 48* 49* 51* 52* 53* 54* 55* 57*; J7 2* 3* 4* 5* 6* 7* 8* 9* 10* 11* 12* 13* 14* 15* 17* 19* 21* 23* 25* 26* 27* 29* 31* 33* 35* 36* 37* 39* 41* 43* 45* 46* 47* 48* 49* 51* 52* 53* 54* 55* 57*

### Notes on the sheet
- PHI PLATFORM
  INTERFACE
- (5.5V)
- (near R75) (1.8V or 3.3V)
- (near C268) (1.8V or 3.3V)
- (near J4) EVM2_PRESENTn
- (3.3V)
- (near J7) EVM2_PRESENTn

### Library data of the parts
C21 C22 C57-C60 C261 C262 C271 C272 = GRM21BR71A106KE51L: CAP, CERM, 10 µF, 10 V, +/- 10%, X7R, 0805; Manufacturer: MuRata; Polarized: N; CompType: Capacitor; Value: 10uF; U/M: EA; Cap_F: 0.00001; Tolerance_%: 10; ESR_ohm: 0.003; Value1: 0.003 ohm; Value2: 10V; TaMin_C: -55; TaMax_C: 125; Cap_Case: 0805; AEC Category: Q200
C53-C56 = GRM155R71C104KA88D: CAP, CERM, 0.1 µF, 16 V, +/- 10%, X7R, 0402; Manufacturer: MuRata; Polarized: N; CompType: Capacitor; Value: 0.1uF; U/M: EA; Cap_F: 0.0000001; Tolerance_%: 10; Value1: Unknown; VDC_V: 16; Value2: 16V; TaMin_C: -55; TaMax_C: 125
C259 C260 C266-C269 = C0603C104J3RACTU: CAP, CERM, 0.1 µF, 25 V, +/- 5%, X7R, 0603; Manufacturer: Kemet; Polarized: N; CompType: Capacitor; Value: 0.1uF; U/M: EA; Cap_F: 0.0000001; Tolerance_%: 5; Value1: Unknown; VDC_V: 25; Value2: 25V; TaMin_C: -55; TaMax_C: 125
J4 J7 = QTH-030-01-L-D-A: Header(Shrouded), 19.7mil, 30x2, Gold, SMT; Manufacturer: Samtec; SymbolCreator: Altium; Pitch_mm: 0.5; Gender: Male; Shrouded: Y; Row_Count: 2
J5 J6 = 61300211121: Header, 2.54 mm, 2x1, Gold, TH; Manufacturer: Wurth Elektronik eiSos; SymbolCreator: a0412235; U/M: EA
R64 R87 = CRCW060310K0FKEA: RES, 10.0 k, 1%, 0.1 W, 0603; Manufacturer: Vishay-Dale; CompType: Resistor; Value: 10.0k; Res_ohm: 10000; Value_Code: 10k0; Tolerance_%: 1; Power_W: 0.1; Value2: 0.1W; VDC_V: 75; TempCo: 100 ppm/C; EIA_Code: E96; U/M: EA
R65-R86 R279 R280 = ERJ-2GE0R00X: RES, 0, 5%, 0.063 W, 0402; Manufacturer: Panasonic; CompType: Resistor; Value: 0; Value_Code: 0000; Tolerance_%: 5; Power_W: 0.063; Value2: 0.063W; VDC_V: 50; TempCo: 600 ppm/C; EIA_Code: E24; U/M: EA; AEC Category: Q200
U13 U14 = BR24G32FVT-3AGE2: I2C BUS EEPROM (2-Wire), TSSOP-B8; Manufacturer: Rohm; SymbolCreator: a0411947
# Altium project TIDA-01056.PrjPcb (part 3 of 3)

## Sheet OPA625 ADC Driver_OPA625 ADC Driver REV1.0.SchDoc
size 762 x 381 mm; Date: Not shown in title block; ApprovedBy: Not shown in title block; CheckedBy: Not shown in title block; Author: Not shown in title block; CompanyName: Not shown in title block; Engineer: Not shown in title block; Organization: Not shown in title block; Address1: Not shown in title block; Address2: Not shown in title block; Address3: Not shown in title block; Address4: Not shown in title block; DocumentNumber: 5; Revision: Use project parameter SCH_Rev; SheetNumber: 5; SheetTotal: 8; PageSetup: Record=PageOptions¦CenterHorizontal=True¦CenterVertical=True¦PrintScale=0.55¦XCorrection=1.00¦YCorrection=1.00¦PrintKind=0¦BorderSize=5000000¦LeftOffset=0¦BottomOffset=0¦Orientation=2¦PaperLength=1000¦PaperWidth=1000¦Scale=100¦PaperSource=15¦PrintQuality=-3¦MediaType=1¦DitherType=10¦PrintScaleMode=1¦PaperKind=11x17¦PaperIndex=17

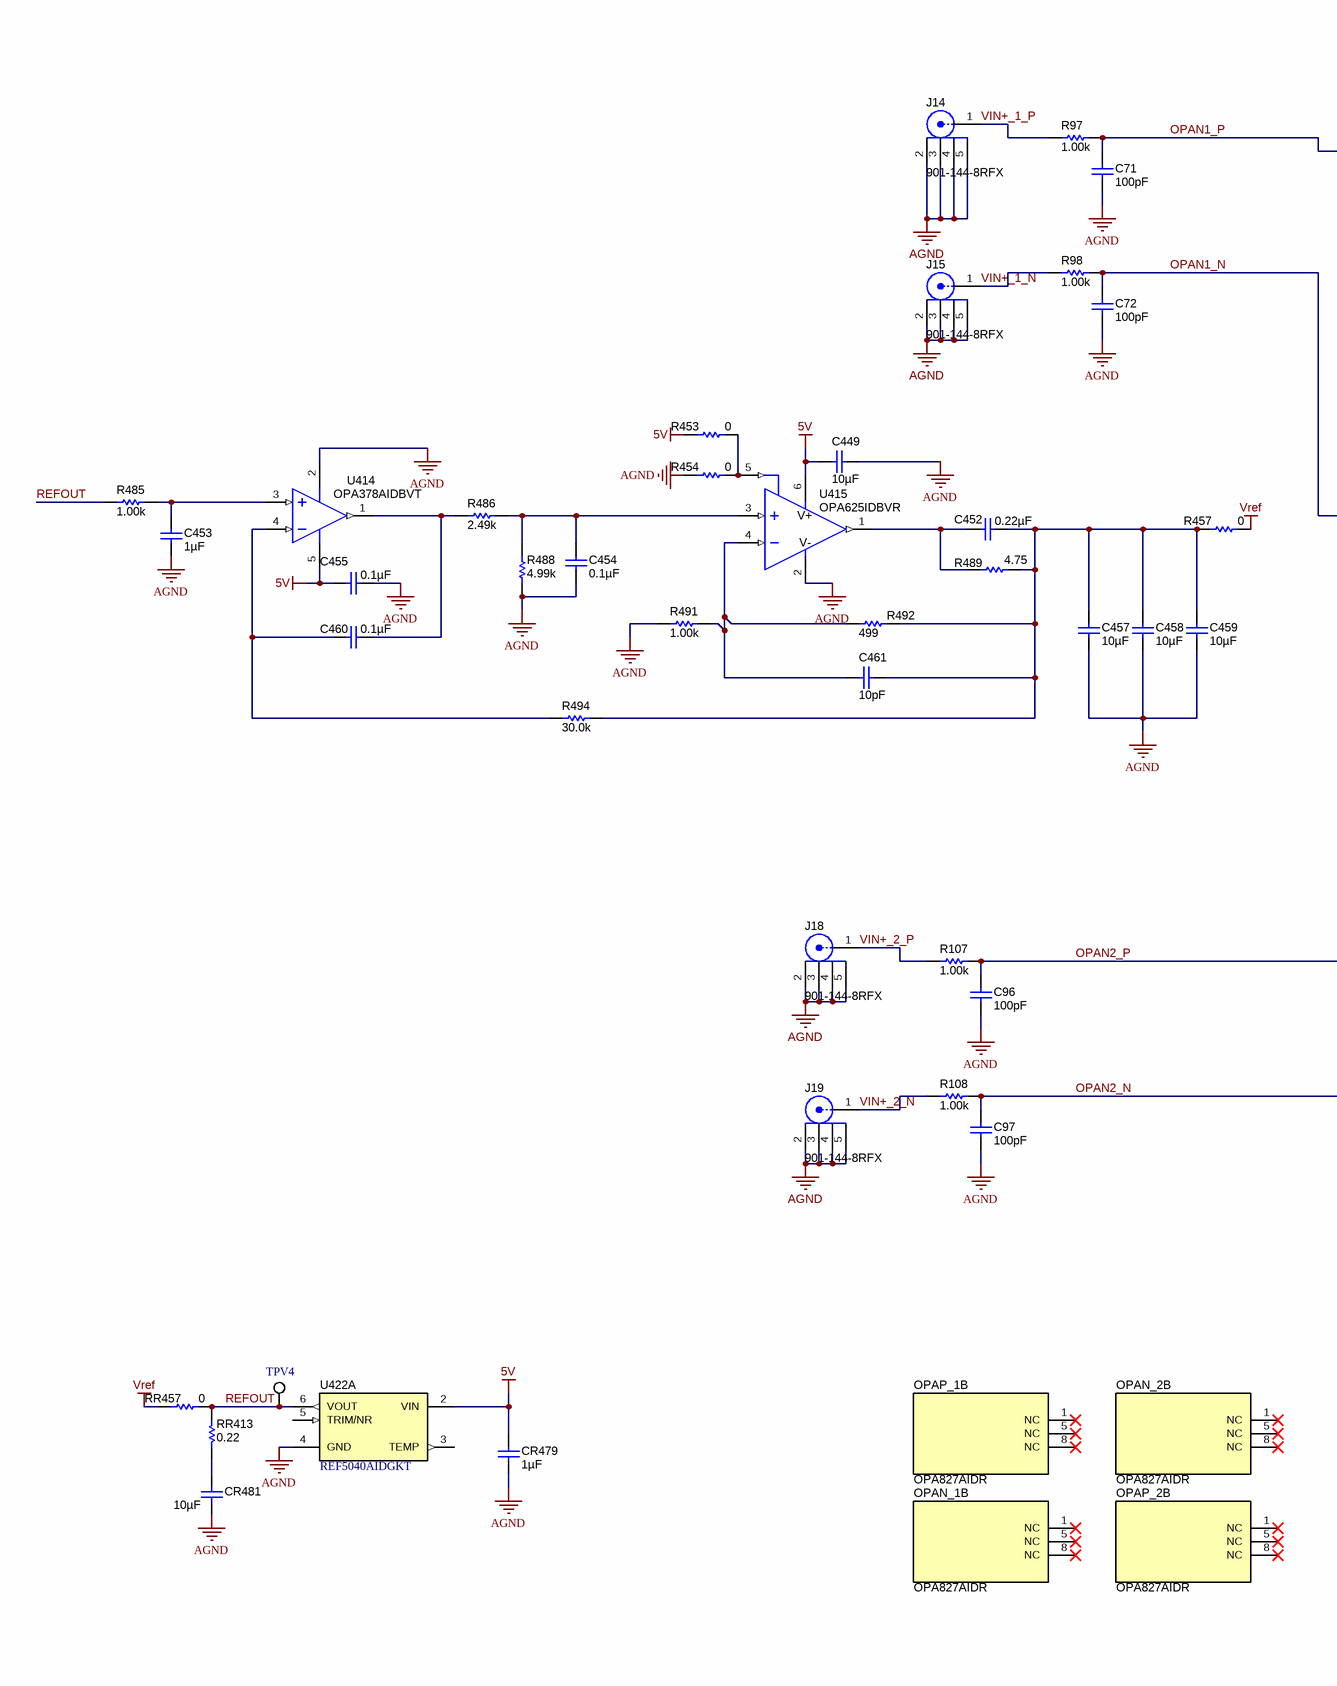
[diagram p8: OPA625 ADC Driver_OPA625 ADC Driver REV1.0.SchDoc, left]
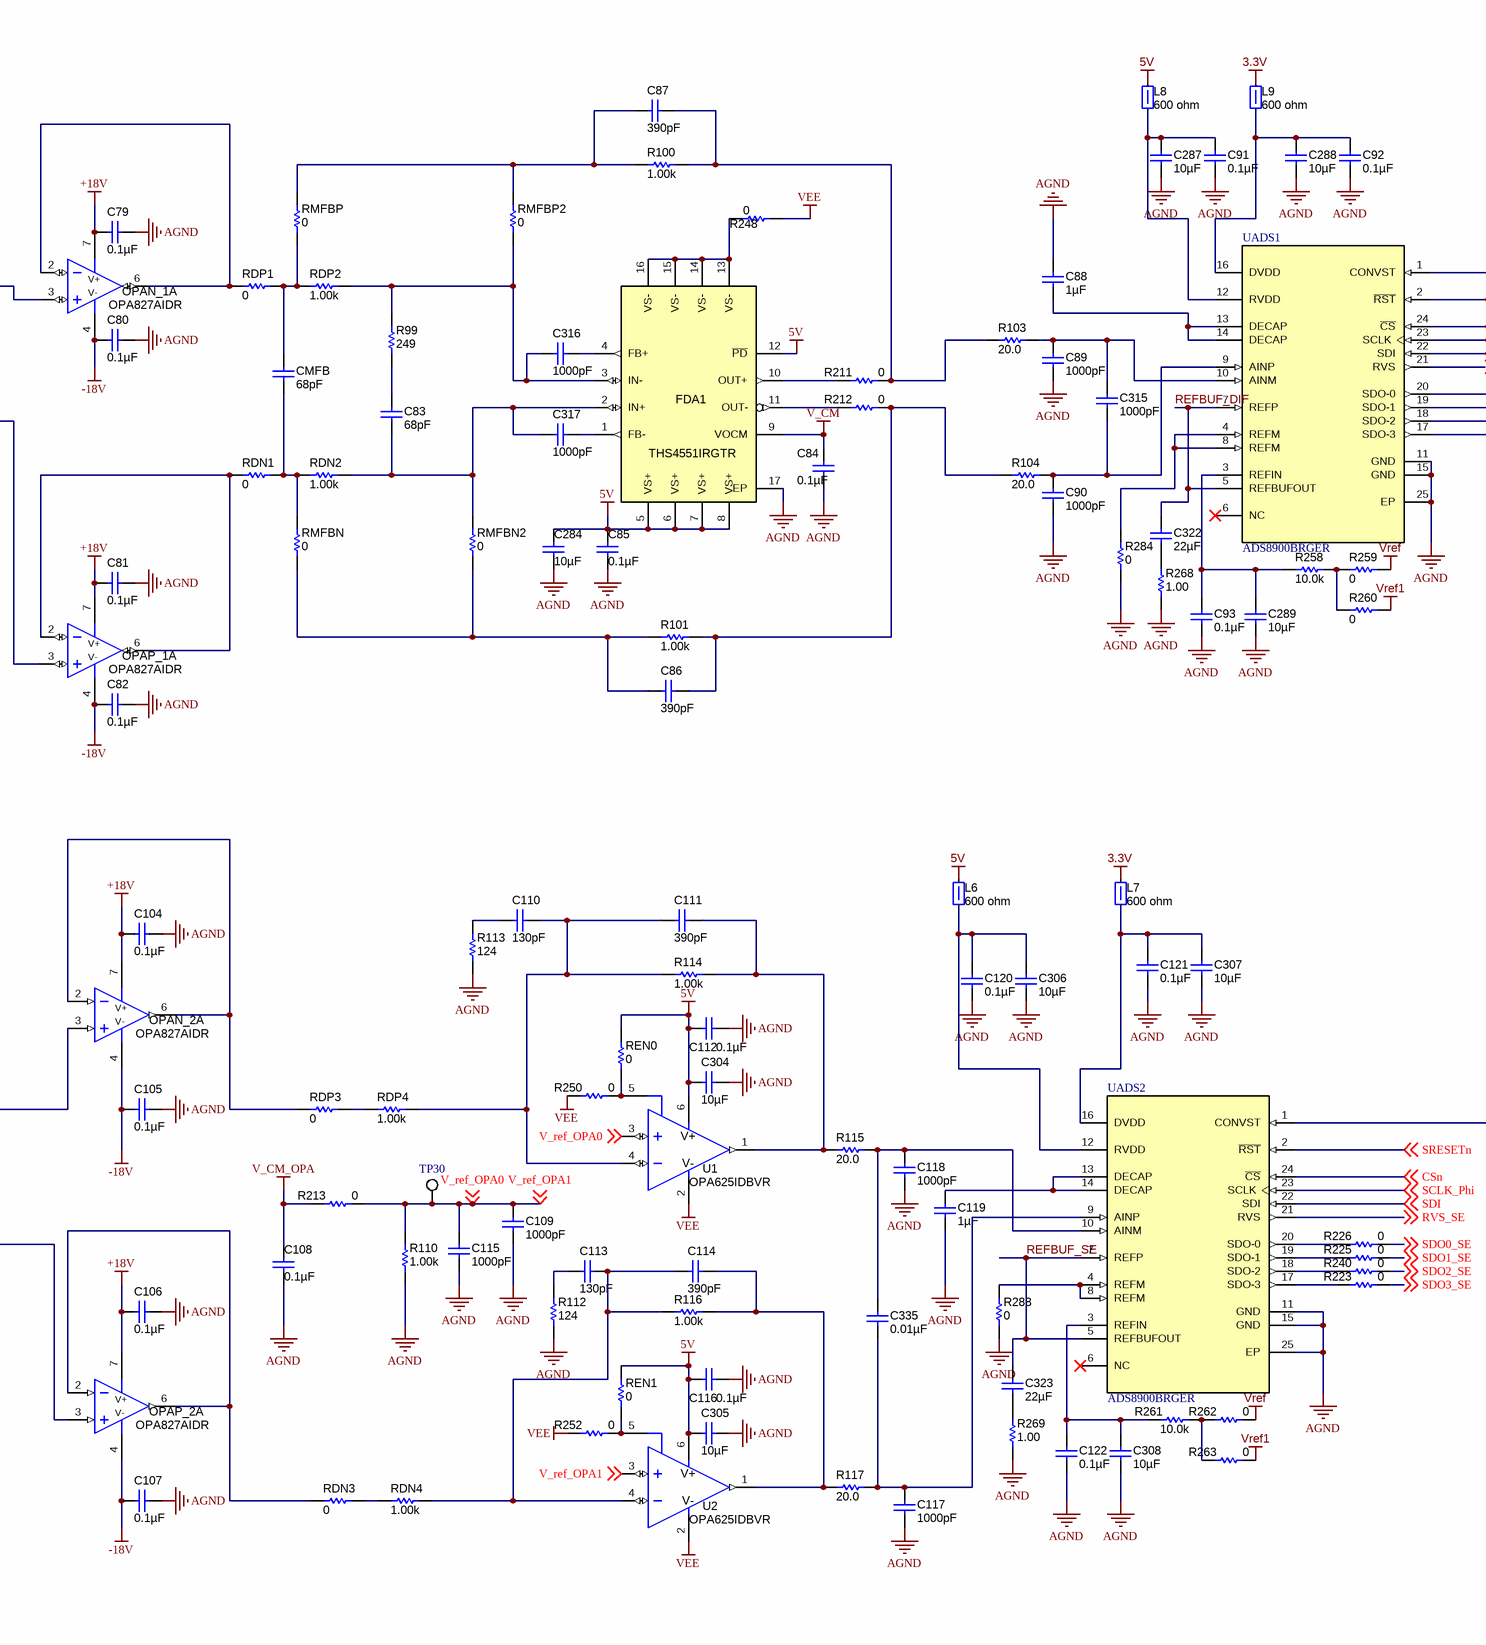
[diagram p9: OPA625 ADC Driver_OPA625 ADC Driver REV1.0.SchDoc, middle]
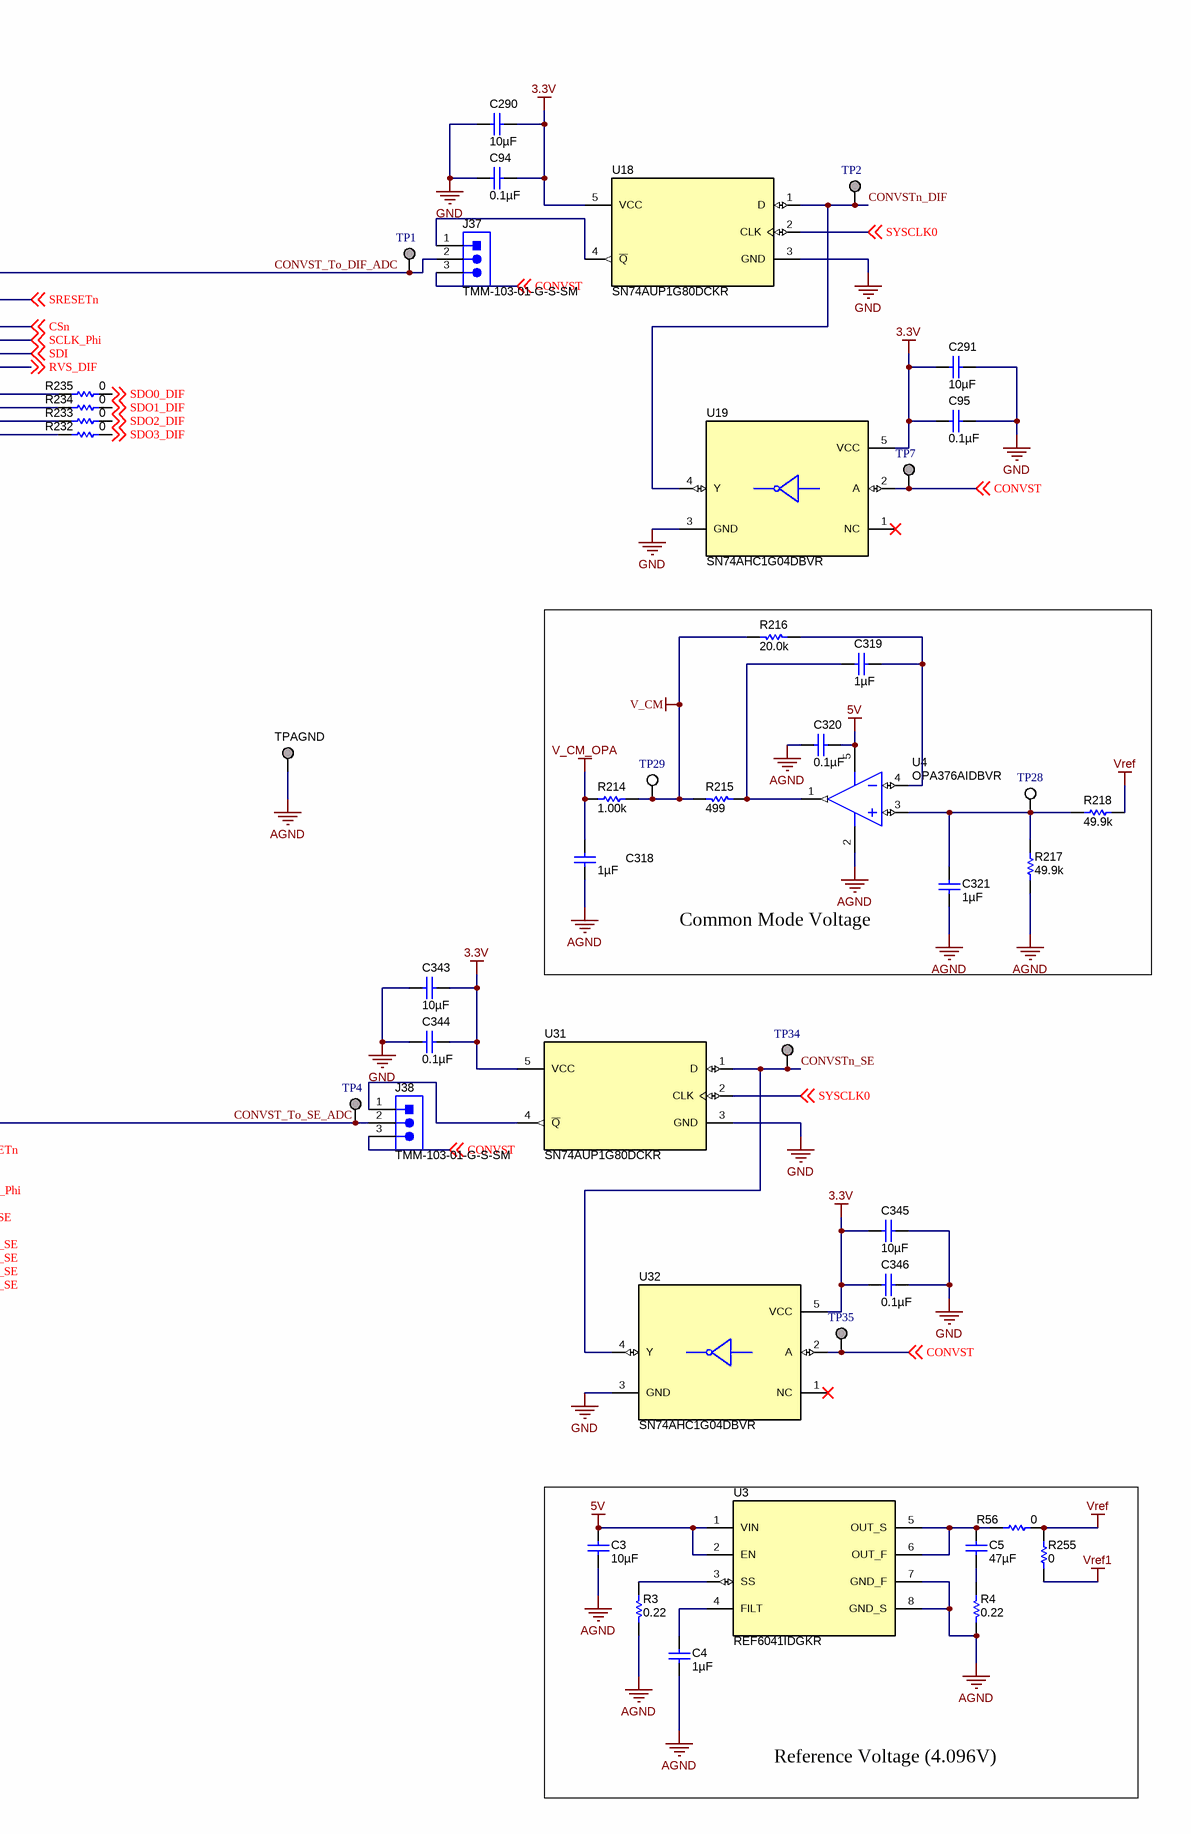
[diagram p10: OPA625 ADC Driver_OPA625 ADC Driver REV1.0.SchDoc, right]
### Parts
C3  ValueDisplayed: 10µF  [0805]  (hidden comment: GRM21BR71A106KE51L)
C4  ValueDisplayed: 1µF  [0603]  (hidden comment: GRM188R71A105KA61D)
C5  ValueDisplayed: 47µF  [1210_270]  (hidden comment: GRM32ER71A476KE15L)
C71  ValueDisplayed: 100pF  [0603]  (hidden comment: GCM1885C2A101JA16D)
C72  ValueDisplayed: 100pF  [0603]  (hidden comment: GCM1885C2A101JA16D)
C79  ValueDisplayed: 0.1µF  [0603]  (hidden comment: GRM188R72A104KA35D)
C80  ValueDisplayed: 0.1µF  [0603]  (hidden comment: GRM188R72A104KA35D)
C81  ValueDisplayed: 0.1µF  [0603]  (hidden comment: GRM188R72A104KA35D)
C82  ValueDisplayed: 0.1µF  [0603]  (hidden comment: GRM188R72A104KA35D)
C83  ValueDisplayed: 68pF  [0603]  (hidden comment: GRM1885C2A680JA01D)
C84  ValueDisplayed: 0.1µF  [0603]  (hidden comment: C0603C104J3RACTU)
C85  ValueDisplayed: 0.1µF  [0603]  (hidden comment: C0603C104J3RACTU)
C86  ValueDisplayed: 390pF  [0603]  (hidden comment: GRM1885C2A391JA01D)
C87  ValueDisplayed: 390pF  [0603]  (hidden comment: GRM1885C2A391JA01D)
C88  ValueDisplayed: 1µF  [0603]  (hidden comment: GRM188R71A105KA61D)
C89  ValueDisplayed: 1000pF  [0603]  (hidden comment: C1608C0G2A102J080AA)
C90  ValueDisplayed: 1000pF  [0603]  (hidden comment: C1608C0G2A102J080AA)
C91  ValueDisplayed: 0.1µF  [0603]  (hidden comment: C0603C104J3RACTU)
C92  ValueDisplayed: 0.1µF  [0603]  (hidden comment: C0603C104J3RACTU)
C93  ValueDisplayed: 0.1µF  [0603]  (hidden comment: C0603C104J3RACTU)
C94  ValueDisplayed: 0.1µF  [0402]  (hidden comment: GRM155R71C104KA88D)
C95  ValueDisplayed: 0.1µF  [0402]  (hidden comment: GRM155R71C104KA88D)
C96  ValueDisplayed: 100pF  [0603]  (hidden comment: GCM1885C2A101JA16D)
C97  ValueDisplayed: 100pF  [0603]  (hidden comment: GCM1885C2A101JA16D)
C104  ValueDisplayed: 0.1µF  [0603]  (hidden comment: GRM188R72A104KA35D)
C105  ValueDisplayed: 0.1µF  [0603]  (hidden comment: GRM188R72A104KA35D)
C106  ValueDisplayed: 0.1µF  [0603]  (hidden comment: GRM188R72A104KA35D)
C107  ValueDisplayed: 0.1µF  [0603]  (hidden comment: GRM188R72A104KA35D)
C108  ValueDisplayed: 0.1µF  [0603]  (hidden comment: C0603C104J3RACTU)
C109  ValueDisplayed: 1000pF  [0603]  (hidden comment: C0603C102J5GAC)
C110  ValueDisplayed: 130pF  [0603]  (hidden comment: GRM1885C2A131JA01D)
C111  ValueDisplayed: 390pF  [0603]  (hidden comment: GRM1885C2A391JA01D)
C112  ValueDisplayed: 0.1µF  [0603]  (hidden comment: C0603C104J3RACTU)
C113  ValueDisplayed: 130pF  [0603]  (hidden comment: GRM1885C2A131JA01D)
C114  ValueDisplayed: 390pF  [0603]  (hidden comment: GRM1885C2A391JA01D)
C115  ValueDisplayed: 1000pF  [0603]  (hidden comment: C0603C102J5GAC)
C116  ValueDisplayed: 0.1µF  [0603]  (hidden comment: C0603C104J3RACTU)
C117  ValueDisplayed: 1000pF  [0603]  (hidden comment: C1608C0G2A102J080AA)
C118  ValueDisplayed: 1000pF  [0603]  (hidden comment: C1608C0G2A102J080AA)
C119  ValueDisplayed: 1µF  [0603]  (hidden comment: GRM188R71A105KA61D)
C120  ValueDisplayed: 0.1µF  [0603]  (hidden comment: C0603C104J3RACTU)
C121  ValueDisplayed: 0.1µF  [0603]  (hidden comment: C0603C104J3RACTU)
C122  ValueDisplayed: 0.1µF  [0603]  (hidden comment: C0603C104J3RACTU)
C284  ValueDisplayed: 10µF  [0805_HV]  (hidden comment: GRM21BR71A106KE51L)
C287  ValueDisplayed: 10µF  [0805_HV]  (hidden comment: GRM21BR71A106KE51L)
C288  ValueDisplayed: 10µF  [0805_HV]  (hidden comment: GRM21BR71A106KE51L)
C289  ValueDisplayed: 10µF  [0805_HV]  (hidden comment: GRM21BR71A106KE51L)
C290  ValueDisplayed: 10µF  [0805_HV]  (hidden comment: GRM21BR71A106KE51L)
C291  ValueDisplayed: 10µF  [0805_HV]  (hidden comment: GRM21BR71A106KE51L)
C304  ValueDisplayed: 10µF  [0805_HV]  (hidden comment: GRM21BR71A106KE51L)
C305  ValueDisplayed: 10µF  [0805_HV]  (hidden comment: GRM21BR71A106KE51L)
C306  ValueDisplayed: 10µF  [0805_HV]  (hidden comment: GRM21BR71A106KE51L)
C307  ValueDisplayed: 10µF  [0805_HV]  (hidden comment: GRM21BR71A106KE51L)
C308  ValueDisplayed: 10µF  [0805_HV]  (hidden comment: GRM21BR71A106KE51L)
C315  ValueDisplayed: 1000pF  [0603]  (hidden comment: C1608C0G2A102J080AA)
C316  ValueDisplayed: 1000pF  [0603]  (hidden comment: C1608C0G2A102J080AA)
C317  ValueDisplayed: 1000pF  [0603]  (hidden comment: C1608C0G2A102J080AA)
C318  ValueDisplayed: 1µF  [0603]  (hidden comment: GRM188R71E105KA12D)
C319  ValueDisplayed: 1µF  [0603]  (hidden comment: GRM188R71E105KA12D)
C320  ValueDisplayed: 0.1µF  [0603]  (hidden comment: C0603C104J3RACTU)
C321  ValueDisplayed: 1µF  [0603]  (hidden comment: GRM188R71E105KA12D)
C322  ValueDisplayed: 22µF  [0603]  (hidden comment: C1608X5R1A226M080AC)
C323  ValueDisplayed: 22µF  [0603]  (hidden comment: C1608X5R1A226M080AC)
C335  ValueDisplayed: 0.01µF  [0603]  (hidden comment: CGA3E2C0G1H103J080AA)
C343  ValueDisplayed: 10µF  [0805_HV]  (hidden comment: GRM21BR71A106KE51L)
C344  ValueDisplayed: 0.1µF  [0402]  (hidden comment: GRM155R71C104KA88D)
C345  ValueDisplayed: 10µF  [0805_HV]  (hidden comment: GRM21BR71A106KE51L)
C346  ValueDisplayed: 0.1µF  [0402]  (hidden comment: GRM155R71C104KA88D)
C449  ValueDisplayed: 10µF  [0603_120]  (hidden comment: ZRB18AD71A106KE01L)
C452  ValueDisplayed: 0.22µF  [0805_HV]  (hidden comment: 0805YC224JAT2A)
C453  ValueDisplayed: 1µF  [0603]  (hidden comment: GRM188R71E105KA12D)
C454  ValueDisplayed: 0.1µF  [0603]  (hidden comment: C0603C104J3RACTU)
C455  ValueDisplayed: 0.1µF  [0603]  (hidden comment: C0603C104J3RACTU)
C457  ValueDisplayed: 10µF  [0603_120]  (hidden comment: ZRB18AD71A106KE01L)
C458  ValueDisplayed: 10µF  [0603_120]  (hidden comment: ZRB18AD71A106KE01L)
C459  ValueDisplayed: 10µF  [0603_120]  (hidden comment: ZRB18AD71A106KE01L)
C460  ValueDisplayed: 0.1µF  [0603]  (hidden comment: C0603C104J3RACTU)
C461  ValueDisplayed: 10pF  [0603]  (hidden comment: C0603C100F5GAC7867)
CMFB  ValueDisplayed: 68pF  [0603]  (hidden comment: GRM1885C2A680JA01D)
CR479  ValueDisplayed: 1µF  [0603]  (hidden comment: GRM188R71E105KA12D)
CR481  ValueDisplayed: 10µF  [0805_HV]  (hidden comment: GRM21BR71A106KE51L)
FDA1  THS4551IRGTR  [RGT0016A]
J14  901-144-8RFX  [Amphenol_901-144-8RFX]
J15  901-144-8RFX  [Amphenol_901-144-8RFX]
J18  901-144-8RFX  [Amphenol_901-144-8RFX]
J19  901-144-8RFX  [Amphenol_901-144-8RFX]
J37  TMM-103-01-G-S-SM  [Samtec_TMM-103-01-x-S-SM]
J38  TMM-103-01-G-S-SM  [Samtec_TMM-103-01-x-S-SM]
L6  value 600 ohm  [0805_HV]  (hidden comment: MPZ2012S601A)
L7  value 600 ohm  [0805_HV]  (hidden comment: MPZ2012S601A)
L8  value 600 ohm  [0805_HV]  (hidden comment: MPZ2012S601A)
L9  value 600 ohm  [0805_HV]  (hidden comment: MPZ2012S601A)
OPAN_1  OPA827AIDR  [D0008A_N]  (parts A,B of 2)
OPAN_2  OPA827AIDR  [D0008A_N]  (parts A,B of 2)
OPAP_1  OPA827AIDR  [D0008A_N]  (parts A,B of 2)
OPAP_2  OPA827AIDR  [D0008A_N]  (parts A,B of 2)
R3  value 0.22  [0603]  (hidden comment: ERJ-3RQFR22V)
R4  value 0.22  [0603]  (hidden comment: ERJ-3RQFR22V)
R56  ValueDisplayed: 0  [0402]  (hidden comment: ERJ-2GE0R00X)
R97  ValueDisplayed: 1.00k  [0603]  (hidden comment: RG1608P-102-B-T5)
R98  ValueDisplayed: 1.00k  [0603]  (hidden comment: RG1608P-102-B-T5)
R99  ValueDisplayed: 249  [0603]  (hidden comment: CRCW0603249RFKEA)
R100  ValueDisplayed: 1.00k  [0603]  (hidden comment: RT0603BRB071KL)
R101  ValueDisplayed: 1.00k  [0603]  (hidden comment: RT0603BRB071KL)
R103  ValueDisplayed: 20.0  [0603]  (hidden comment: RT0603BRD0720RL)
R104  ValueDisplayed: 20.0  [0603]  (hidden comment: RT0603BRD0720RL)
R107  ValueDisplayed: 1.00k  [0603]  (hidden comment: RG1608P-102-B-T5)
R108  ValueDisplayed: 1.00k  [0603]  (hidden comment: RG1608P-102-B-T5)
R110  ValueDisplayed: 1.00k  [0603]  (hidden comment: RG1608P-102-B-T5)
R112  ValueDisplayed: 124  [0603]  (hidden comment: RC0603FR-07124RL)
R113  ValueDisplayed: 124  [0603]  (hidden comment: RC0603FR-07124RL)
R114  ValueDisplayed: 1.00k  [0603]  (hidden comment: RT0603BRB071KL)
R115  ValueDisplayed: 20.0  [0603]  (hidden comment: RT0603BRD0720RL)
R116  ValueDisplayed: 1.00k  [0603]  (hidden comment: RT0603BRB071KL)
R117  ValueDisplayed: 20.0  [0603]  (hidden comment: RT0603BRD0720RL)
R211  ValueDisplayed: 0  [0402]  (hidden comment: ERJ-2GE0R00X)
R212  ValueDisplayed: 0  [0402]  (hidden comment: ERJ-2GE0R00X)
R213  ValueDisplayed: 0  [0402]  (hidden comment: ERJ-2GE0R00X)
R214  ValueDisplayed: 1.00k  [0603]  (hidden comment: RG1608P-102-B-T5)
R215  ValueDisplayed: 499  [0603]  (hidden comment: RG1608P-4990-B-T5)
R216  ValueDisplayed: 20.0k  [0603]  (hidden comment: RG1608P-203-B-T5)
R217  ValueDisplayed: 49.9k  [0603]  (hidden comment: RG1608P-4992-B-T5)
R218  ValueDisplayed: 49.9k  [0603]  (hidden comment: RG1608P-4992-B-T5)
R223  ValueDisplayed: 0  [0402]  (hidden comment: ERJ-2GE0R00X)
R225  ValueDisplayed: 0  [0402]  (hidden comment: ERJ-2GE0R00X)
R226  ValueDisplayed: 0  [0402]  (hidden comment: ERJ-2GE0R00X)
R232  ValueDisplayed: 0  [0402]  (hidden comment: ERJ-2GE0R00X)
R233  ValueDisplayed: 0  [0402]  (hidden comment: ERJ-2GE0R00X)
R234  ValueDisplayed: 0  [0402]  (hidden comment: ERJ-2GE0R00X)
R235  ValueDisplayed: 0  [0402]  (hidden comment: ERJ-2GE0R00X)
R240  ValueDisplayed: 0  [0402]  (hidden comment: ERJ-2GE0R00X)
R248  ValueDisplayed: 0  [0402]  (hidden comment: ERJ-2GE0R00X)
R250  ValueDisplayed: 0  [0402]  (hidden comment: ERJ-2GE0R00X)
R252  ValueDisplayed: 0  [0402]  (hidden comment: ERJ-2GE0R00X)
R255  ValueDisplayed: 0  [0402]  (hidden comment: ERJ-2GE0R00X)
R258  ValueDisplayed: 10.0k  [0603]  (hidden comment: RG1608P-103-B-T5)
R259  ValueDisplayed: 0  [0402]  (hidden comment: ERJ-2GE0R00X)
R260  ValueDisplayed: 0  [0402]  (hidden comment: ERJ-2GE0R00X)
R261  ValueDisplayed: 10.0k  [0603]  (hidden comment: RG1608P-103-B-T5)
R262  ValueDisplayed: 0  [0402]  (hidden comment: ERJ-2GE0R00X)
R263  ValueDisplayed: 0  [0402]  (hidden comment: ERJ-2GE0R00X)
R268  ValueDisplayed: 1.00  [0603]  (hidden comment: CRCW06031R00FKEA)
R269  ValueDisplayed: 1.00  [0603]  (hidden comment: CRCW06031R00FKEA)
R284  ValueDisplayed: 0  [0402]  (hidden comment: ERJ-2GE0R00X)
R288  ValueDisplayed: 0  [0402]  (hidden comment: ERJ-2GE0R00X)
R453  ValueDisplayed: 0  [0402]  (hidden comment: ERJ-2GE0R00X)
R454  ValueDisplayed: 0  [0402]  (hidden comment: ERJ-2GE0R00X)
R457  ValueDisplayed: 0  [0402]  (hidden comment: ERJ-2GE0R00X)
R485  ValueDisplayed: 1.00k  [0603]  (hidden comment: RG1608P-102-B-T5)
R486  ValueDisplayed: 2.49k  [0603]  (hidden comment: RG1608P-2491-B-T5)
R488  ValueDisplayed: 4.99k  [0603]  (hidden comment: RG1608P-4991-B-T5)
R489  ValueDisplayed: 4.75  [0603]  (hidden comment: CRCW06034R75FKEA)
R491  ValueDisplayed: 1.00k  [0603]  (hidden comment: RG1608P-102-B-T5)
R492  ValueDisplayed: 499  [0603]  (hidden comment: RG1608P-4990-B-T5)
R494  ValueDisplayed: 30.0k  [0603]  (hidden comment: RG1608P-303-B-T5)
RDN1  ValueDisplayed: 0  [0603]  (hidden comment: ERJ-3GEY0R00V)
RDN2  ValueDisplayed: 1.00k  [0603]  (hidden comment: RT0603BRB071KL)
RDN3  ValueDisplayed: 0  [0603]  (hidden comment: ERJ-3GEY0R00V)
RDN4  ValueDisplayed: 1.00k  [0603]  (hidden comment: RT0603BRB071KL)
RDP1  ValueDisplayed: 0  [0603]  (hidden comment: ERJ-3GEY0R00V)
RDP2  ValueDisplayed: 1.00k  [0603]  (hidden comment: RT0603BRB071KL)
RDP3  ValueDisplayed: 0  [0603]  (hidden comment: ERJ-3GEY0R00V)
RDP4  ValueDisplayed: 1.00k  [0603]  (hidden comment: RT0603BRB071KL)
REN0  ValueDisplayed: 0  [0402]  (hidden comment: ERJ-2GE0R00X)
REN1  ValueDisplayed: 0  [0402]  (hidden comment: ERJ-2GE0R00X)
RMFBN  ValueDisplayed: 0  [0402]  (hidden comment: ERJ-2GE0R00X)
RMFBN2  ValueDisplayed: 0  [0402]  (hidden comment: ERJ-2GE0R00X)
RMFBP  ValueDisplayed: 0  [0402]  (hidden comment: ERJ-2GE0R00X)
RMFBP2  ValueDisplayed: 0  [0402]  (hidden comment: ERJ-2GE0R00X)
RR413  ValueDisplayed: 0.22  [0603]  (hidden comment: ERJ-3RQFR22V)
RR457  ValueDisplayed: 0  [0402]  (hidden comment: ERJ-2GE0R00X)
TP1  Pogo Pad  [PogoPad]  (value not drawn)  (no BOM)
TP2  Pogo Pad  [PogoPad]  (value not drawn)  (no BOM)
TP4  Pogo Pad  [PogoPad]  (value not drawn)  (no BOM)
TP7  Pogo Pad  [PogoPad]  (value not drawn)  (no BOM)
TP28  5015  [Testpoint_Keystone_Miniature]  (value not drawn)
TP29  5015  [Testpoint_Keystone_Miniature]  (value not drawn)
TP30  5015  [Testpoint_Keystone_Miniature]  (value not drawn)
TP34  Pogo Pad  [PogoPad]  (value not drawn)  (no BOM)
TP35  Pogo Pad  [PogoPad]  (value not drawn)  (no BOM)
TPAGND  Pogo Pad  [PogoPad]  (value not drawn)  (no BOM)
TPV4  5015  [Testpoint_Keystone_Miniature]  (value not drawn)
U1  OPA625IDBVR  [DBV0006A_N]
U2  OPA625IDBVR  [DBV0006A_N]
U3  REF6041IDGKR  [DGK0008A_N]
U4  OPA376AIDBVR  [DBV0005A_N]
U18  SN74AUP1G80DCKR  [DCK0005A_N]
U19  SN74AHC1G04DBVR  [DBV0005A_N]
U31  SN74AUP1G80DCKR  [DCK0005A_N]
U32  SN74AHC1G04DBVR  [DBV0005A_N]
U414  OPA378AIDBVT  [DBV0005A_N]
U415  OPA625IDBVR  [DBV0006A_N]
U422  REF5040AIDGKT  [DGK0008A_N]  (part A of 2)
UADS1  ADS8900BRGER  [RGE0024H]
UADS2  ADS8900BRGER  [RGE0024H]

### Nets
3.3V: C94.2 C95.2 C290.1 C291.2 C343.1 C344.2 C345.2 C346.2 L7.1 L9.1 U18.5(VCC) U19.5(VCC) U31.5(VCC) U32.5(VCC)
5V: C3.2 C85.1 C112.2 C116.2 C284.1 C304.1 C305.1 C320.2 C449.2 C455.2 CR479.1 FDA1.5(VS+) FDA1.6(VS+) FDA1.7(VS+) FDA1.8(VS+) FDA1.12(~{PD}) L6.1 L8.1 R453.1 REN0.1 REN1.1 U1.6(V+) U2.6(V+) U3.1(VIN) U3.2(EN) U4.5(V+) U414.5(V+) U415.6(V+) U422.2(VIN)
+18V: C79.2 C81.2 C104.2 C106.2 OPAN_1.7(V+) OPAN_2.7(V+) OPAP_1.7(V+) OPAP_2.7(V+)
-18V: C80.2 C82.2 C105.2 C107.2 OPAN_1.4(V-) OPAN_2.4(V-) OPAP_1.4(V-) OPAP_2.4(V-)
AGND: C3.1 C4.2 C71.1 C72.1 C79.1 C80.1 C81.1 C82.1 C84.2 C85.2 C88.1 C89.2 C90.2 C91.1 C92.2 C93.2 C96.1 C97.1 C104.1 C105.1 C106.1 C107.1 C108.2 C109.2 C112.1 C115.2 C116.1 C117.2 C118.2 C119.2 C120.1 C121.2 C122.2 C284.2 C287.2 C288.2 C289.2 C304.2 C305.2 C306.2 C307.2 C308.2 C318.2 C320.1 C321.2 C449.1 C453.2 C454.2 C455.1 C457.2 C458.2 C459.2 CR479.2 CR481.2 FDA1.17(EP) J14.2 J14.3 J14.4 J14.5 J15.2 J15.3 J15.4 J15.5 J18.2 J18.3 J18.4 J18.5 J19.2 J19.3 J19.4 J19.5 R3.1 R4.2 R110.1 R112.1 R113.1 R217.1 R268.1 R269.1 R284.1 R288.1 R454.1 R488.1 R491.1 TPAGND.1 U3.7(GND_F) U3.8(GND_S) U4.2(V-) U414.2(V-) U415.2(V-) U422.4(GND) UADS1.11(GND) UADS1.15(GND) UADS1.25(EP) UADS2.11(GND) UADS2.15(GND) UADS2.25(EP)
GND: C94.1 C95.1 C290.2 C291.1 C343.2 C344.1 C345.1 C346.1 U18.3(GND) U19.3(GND) U31.3(GND) U32.3(GND)
V_CM: C84.1 FDA1.9(VOCM) R214.2 R215.2 R216.2 TP29.1
V_CM_OPA: C108.1 C318.1 R213.1 R214.1
VEE: R248.2 R250.1 R252.1 U1.2(V-) U2.2(V-)
Vref: R56.2 R218.2 R255.2 R259.1 R262.2 R457.2 RR457.1
Vref1: R255.1 R260.1 R263.2
CONVST: J37.3 J38.3 TP7.1 TP35.1 U19.2(A) U32.2(A) ; off-sheet CONVST
CONVST_To_DIF_ADC: J37.2 TP1.1 UADS1.1(CONVST)
CONVST_To_SE_ADC: J38.2 TP4.1 UADS2.1(CONVST)
CONVSTn_DIF: TP2.1 U18.1(D) U19.4(Y)
CONVSTn_SE: TP34.1 U31.1(D) U32.4(Y)
CSn: UADS1.24(~{CS}) UADS2.24(~{CS}) ; off-sheet CSn
OPAN1_N: C72.2 OPAP_1.3(IN+) R98.2
OPAN1_P: C71.2 OPAN_1.3(IN+) R97.2
OPAN2_N: C97.2 OPAP_2.3(IN+) R108.2
OPAN2_P: C96.2 OPAN_2.3(IN+) R107.2
REFBUF_DIF: C322.1 UADS1.5(REFBUFOUT) UADS1.7(REFP)
REFBUF_SE: C323.1 UADS2.5(REFBUFOUT) UADS2.7(REFP)
REFOUT: R485.1 RR413.2 RR457.2 TPV4.1 U422.6(VOUT)
RVS_DIF: UADS1.21(RVS) ; off-sheet RVS_DIF
RVS_SE: UADS2.21(RVS) ; off-sheet RVS_SE
SCLK_Phi: UADS1.23(SCLK) UADS2.23(SCLK) ; off-sheet SCLK_Phi
SDI: UADS1.22(SDI) UADS2.22(SDI) ; off-sheet SDI
SDO0_DIF: R235.2 ; off-sheet SDO0_DIF
SDO0_SE: R226.2 ; off-sheet SDO0_SE
SDO1_DIF: R234.2 ; off-sheet SDO1_DIF
SDO1_SE: R225.2 ; off-sheet SDO1_SE
SDO2_DIF: R233.2 ; off-sheet SDO2_DIF
SDO2_SE: R240.2 ; off-sheet SDO2_SE
SDO3_DIF: R232.2 ; off-sheet SDO3_DIF
SDO3_SE: R223.2 ; off-sheet SDO3_SE
SRESETn: UADS1.2(~{RST}) UADS2.2(~{RST}) ; off-sheet SRESETn
SYSCLK0: U18.2(CLK) U31.2(CLK) ; off-sheet SYSCLK0
V_ref_OPA0: C109.1 C115.1 R110.2 R213.2 TP30.1 U1.3(IN+) U2.3(IN+) ; off-sheet V_ref_OPA0, off-sheet V_ref_OPA1  [also labelled V_ref_OPA1]
VIN+_1_N: J15.1 R98.1
VIN+_1_P: J14.1 R97.1
VIN+_2_N: J19.1 R108.1
VIN+_2_P: J18.1 R107.1
NetC4_1: C4.1 U3.4(FILT)
NetC5_1: C5.1 R56.1 U3.5(OUT_S) U3.6(OUT_F)
NetC5_2: C5.2 R4.1
NetC83_1: C83.1 R99.1
NetC83_2: C83.2 C317.2 FDA1.2(IN+) RDN2.1 RMFBN2.1
NetC86_1: C86.1 R101.1 R104.1 R212.2
NetC86_2: C86.2 R101.2 RMFBN.2 RMFBN2.2
NetC87_1: C87.1 R100.1 R103.1 R211.2
NetC87_2: C87.2 R100.2 RMFBP.1 RMFBP2.1
NetC88_2: C88.2 UADS1.13(DECAP) UADS1.14(DECAP)
NetC89_1: C89.1 C315.1 R103.2 UADS1.10(AINM)
NetC90_1: C90.1 C315.2 R104.2 UADS1.9(AINP)
NetC91_2: C91.2 C287.1 L8.2 UADS1.12(RVDD)
NetC92_1: C92.1 C288.1 L9.2 UADS1.16(DVDD)
NetC93_1: C93.1 C289.1 R258.1 UADS1.3(REFIN)
NetC110_1: C110.1 R113.2
NetC110_2: C110.2 C111.2 R114.1 RDP4.1 U1.4(IN-)
NetC111_1: C111.1 R114.2 R115.1 U1.1(OUT)
NetC113_1: C113.1 C114.2 R116.1 RDN4.1 U2.4(IN-)
NetC113_2: C113.2 R112.2
NetC114_1: C114.1 R116.2 R117.1 U2.1(OUT)
NetC117_1: C117.1 C335.2 R117.2 UADS2.9(AINP)
NetC118_1: C118.1 C335.1 R115.2 UADS2.10(AINM)
NetC119_1: C119.1 UADS2.13(DECAP) UADS2.14(DECAP)
NetC120_2: C120.2 C306.1 L6.2 UADS2.12(RVDD)
NetC121_1: C121.1 C307.1 L7.2 UADS2.16(DVDD)
NetC122_1: C122.1 C308.1 R261.1 UADS2.3(REFIN)
NetC316_1: C316.1 FDA1.4(FB+)
NetC316_2: C316.2 FDA1.3(IN-) R99.2 RDP2.1 RMFBP2.2
NetC317_1: C317.1 FDA1.1(FB-)
NetC319_1: C319.1 R215.1 U4.1(OUT)
NetC319_2: C319.2 R216.1 U4.4(IN-)
NetC321_1: C321.1 R217.2 R218.1 TP28.1 U4.3(IN+)
NetC322_2: C322.2 R268.2
NetC323_2: C323.2 R269.2
NetC452_1: C452.1 C457.1 C458.1 C459.1 C461.1 R457.1 R489.2 R492.2 R494.2
NetC452_2: C452.2 R489.1 U415.1(OUT)
NetC453_1: C453.1 R485.2 U414.3(IN+)
NetC454_1: C454.1 R486.2 R488.2 U415.3(IN+)
NetC460_1: C460.1 R486.1 U414.1(OUT)
NetC460_2: C460.2 R494.1 U414.4(IN-)
NetC461_2: C461.2 R491.2 R492.1 U415.4(IN-)
NetCMFB_1: CMFB.1 RDP1.2 RDP2.2 RMFBP.2
NetCMFB_2: CMFB.2 RDN1.2 RDN2.2 RMFBN.1
NetCR481_1: CR481.1 RR413.1
NetFDA1_10: FDA1.10(OUT+) R211.1
NetFDA1_11: FDA1.11(OUT-) R212.1
NetFDA1_13: FDA1.13(VS-) FDA1.14(VS-) FDA1.15(VS-) FDA1.16(VS-) R248.1
NetJ37_1: J37.1 U18.4(~{Q})
NetJ38_1: J38.1 U31.4(~{Q})
NetOPAN_1_2: OPAN_1.2(IN-) OPAN_1.6(OUT) RDP1.1
NetOPAN_2_2: OPAN_2.2(IN-) OPAN_2.6(OUT) RDP3.1
NetOPAP_1_2: OPAP_1.2(IN-) OPAP_1.6(OUT) RDN1.1
NetOPAP_2_2: OPAP_2.2(IN-) OPAP_2.6(OUT) RDN3.1
NetR3_2: R3.2 U3.3(SS)
NetR223_1: R223.1 UADS2.17(SDO-3)
NetR225_1: R225.1 UADS2.19(SDO-1)
NetR226_1: R226.1 UADS2.20(SDO-0)
NetR232_1: R232.1 UADS1.17(SDO-3)
NetR233_1: R233.1 UADS1.18(SDO-2)
NetR234_1: R234.1 UADS1.19(SDO-1)
NetR235_1: R235.1 UADS1.20(SDO-0)
NetR240_1: R240.1 UADS2.18(SDO-2)
NetR250_2: R250.2 REN0.2 U1.5(MODE)
NetR252_2: R252.2 REN1.2 U2.5(MODE)
NetR258_2: R258.2 R259.2 R260.2
NetR261_2: R261.2 R262.1 R263.1
NetR284_2: R284.2 UADS1.4(REFM) UADS1.8(REFM)
NetR288_2: R288.2 UADS2.4(REFM) UADS2.8(REFM)
NetR453_2: R453.2 R454.2 U415.5(MODE)
NetRDN3_2: RDN3.2 RDN4.2
NetRDP3_2: RDP3.2 RDP4.2

Not connected (* = marked no-connect by the designer): OPAN_1 1(NC)* 5(NC)* 8(NC)*; OPAN_2 1(NC)* 5(NC)* 8(NC)*; OPAP_1 1(NC)* 5(NC)* 8(NC)*; OPAP_2 1(NC)* 5(NC)* 8(NC)*; U19 1(NC)*; U32 1(NC)*; U422 3(TEMP) 5(TRIM/NR); UADS1 6(NC)*; UADS2 6(NC)*

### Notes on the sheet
- Common Mode Voltage
- Reference Voltage (4.096V)

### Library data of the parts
C3 = GRM21BR71A106KE51L: CAP, CERM, 10uF, 10V, +/-10%, X7R, 0805; Manufacturer: MuRata; Polarized: N; CompType: Capacitor; U/M: EA; Cap_F: 0.00001; Tolerance_%: 10; ESR_Ohm: 0.003; Value1: 0.003 ohm; TaMin_C: -55; TaMax_C: 125
C4 = GRM188R71A105KA61D: CAP, CERM, 1uF, 10V, +/-10%, X7R, 0603; Manufacturer: MuRata; Polarized: N; CompType: Capacitor; U/M: EA; Cap_F: 0.000001; Tolerance_%: 10; ESR_Ohm: 0.011; Value1: 0.011 ohm; TaMin_C: -55; TaMax_C: 125
C5 = GRM32ER71A476KE15L: CAP, CERM, 47 µF, 10 V, +/- 10%, X7R, 1210; Manufacturer: MuRata; Polarized: N; CompType: Capacitor; Value: 47uF; U/M: EA; Cap_F: 0.000047; Tolerance_%: 10; Value1: Unknown; Value2: 10V; TaMin_C: -55; TaMax_C: 125; Cap_Case: 1210; SizeArea_mm2: 8; SizeAreaWB_mm2: 14.7; SizeX_mm: 3.2; SizeY_mm: 2.5; SizeZ_mm: 2.7; AEC Category: Q200
C71 C72 C96 C97 = GCM1885C2A101JA16D: CAP, CERM, 100 pF, 100 V, +/- 5%, C0G/NP0, AEC-Q200 Grade 1, 0603; Manufacturer: MuRata; Polarized: N; CompType: Capacitor; Value: 100pF; U/M: EA; Cap_F: 0.0000000001; Tolerance_%: 5; Value1: Unknown; VDC_V: 100; Value2: 100V; TaMin_C: -55; TaMax_C: 125; SizeArea_mm2: 1.28; SizeAreaWB_mm2: 4.68; SizeX_mm: 1.6; SizeY_mm: 0.8; SizeZ_mm: 1; AEC Category: Q200; AEC Qualified: Y
C79-C82 C104-C107 = GRM188R72A104KA35D: CAP, CERM, 0.1 µF, 100 V, +/- 10%, X7R, 0603; Manufacturer: MuRata; Polarized: N; CompType: Capacitor; Value: 0.1uF; U/M: EA; Cap_F: 0.0000001; Tolerance_%: 10; Value1: Unknown; VDC_V: 100; Value2: 100V; TaMin_C: -55; TaMax_C: 125; SizeArea_mm2: 1.28; SizeAreaWB_mm2: 4.68; SizeX_mm: 1.6; SizeY_mm: 0.8; SizeZ_mm: 1; AEC Category: Q200
C83 CMFB = GRM1885C2A680JA01D: CAP, CERM, 68 pF, 100 V, +/- 5%, C0G/NP0, 0603; Manufacturer: MuRata; Polarized: N; CompType: Capacitor; Value: 68pF; U/M: EA; Cap_F: 0.000000000068; Tolerance_%: 5; Value1: Unknown; VDC_V: 100; Value2: 100V; TaMin_C: -55; TaMax_C: 125; SizeArea_mm2: 1.28; SizeAreaWB_mm2: 4.68; SizeX_mm: 1.6; SizeY_mm: 0.8; SizeZ_mm: 1; AEC Category: Q200
C84 C85 C91 C92 C108 C112 C116 C120-C122 C454 C455 C460 = C0603C104J3RACTU: CAP, CERM, 0.1 µF, 25 V, +/- 5%, X7R, 0603; Manufacturer: Kemet; Polarized: N; CompType: Capacitor; Value: 0.1uF; U/M: EA; Cap_F: 0.0000001; Tolerance_%: 5; Value1: Unknown; VDC_V: 25; Value2: 25V; TaMin_C: -55; TaMax_C: 125
C86 C87 C111 C114 = GRM1885C2A391JA01D: CAP, CERM, 390 pF, 100 V, +/- 5%, C0G/NP0, 0603; Manufacturer: MuRata; Polarized: N; CompType: Capacitor; Value: 390pF; U/M: EA; Cap_F: 0.00000000039; Tolerance_%: 5; Value1: Unknown; VDC_V: 100; Value2: 100V; TaMin_C: -55; TaMax_C: 125; SizeArea_mm2: 1.28; SizeAreaWB_mm2: 4.68; SizeX_mm: 1.6; SizeY_mm: 0.8; SizeZ_mm: 1; AEC Category: Q200
C88 C119 = GRM188R71A105KA61D: CAP, CERM, 1 µF, 10 V, +/- 10%, X7R, 0603; Manufacturer: MuRata; Polarized: N; CompType: Capacitor; Value: 1uF; U/M: EA; Cap_F: 0.000001; Tolerance_%: 10; ESR_ohm: 0.011; Value1: 0.011 ohm; Value2: 10V; TaMin_C: -55; TaMax_C: 125; SizeArea_mm2: 1.28; SizeAreaWB_mm2: 4.68; SizeX_mm: 1.6; SizeY_mm: 0.8; SizeZ_mm: 1; AEC Category: Q200
C89 C90 C117 C118 C315-C317 = C1608C0G2A102J080AA: CAP, CERM, 1000 pF, 100 V, +/- 5%, C0G/NP0, 0603; Manufacturer: TDK; Polarized: N; CompType: Capacitor; Value: 1000pF; U/M: EA; Cap_F: 0.000000001; Tolerance_%: 5; ESR_ohm: 0.0589; Value1: 0.0589 ohm; VDC_V: 100; Value2: 100V; TaMin_C: -55; TaMax_C: 125; SizeArea_mm2: 1.28; SizeAreaWB_mm2: 4.68; SizeX_mm: 1.6; SizeY_mm: 0.8; SizeZ_mm: 1; AEC Category: Q200
C93 = C0603C104J3RACTU: CAP, CERM, 0.1 µF, 25 V, +/- 5%, X7R, 0603; Manufacturer: Kemet; Polarized: N; CompType: Capacitor; Value: 0.1uF; U/M: EA; Cap_F: 0.0000001; Tolerance_%: 5; Value1: Unknown; VDC_V: 25; Value2: 25V; TaMin_C: -55; TaMax_C: 125; SizeArea_mm2: 1.28; SizeAreaWB_mm2: 4.68; SizeX_mm: 1.6; SizeY_mm: 0.8; SizeZ_mm: 1; AEC Category: Q200
C94 C95 C344 C346 = GRM155R71C104KA88D: CAP, CERM, 0.1 µF, 16 V, +/- 10%, X7R, 0402; Manufacturer: MuRata; Polarized: N; CompType: Capacitor; Value: 0.1uF; U/M: EA; Cap_F: 0.0000001; Tolerance_%: 10; Value1: Unknown; VDC_V: 16; Value2: 16V; TaMin_C: -55; TaMax_C: 125
C109 C115 = C0603C102J5GAC: CAP, CERM, 1000 pF, 50 V, +/- 5%, C0G/NP0, 0603; Manufacturer: Kemet; Polarized: N; CompType: Capacitor; Value: 1000pF; U/M: EA; Cap_F: 0.000000001; Tolerance_%: 5; Value1: Unknown; VDC_V: 50; Value2: 50V; TaMin_C: -55; TaMax_C: 125; SizeArea_mm2: 1.28; SizeAreaWB_mm2: 4.68; SizeX_mm: 1.6; SizeY_mm: 0.8; SizeZ_mm: 1; AEC Category: Q200
C110 C113 = GRM1885C2A131JA01D: CAP, CERM, 130 pF, 100 V, +/- 5%, C0G/NP0, 0603; Manufacturer: MuRata; Polarized: N; CompType: Capacitor; Value: 130pF; U/M: EA; Cap_F: 0.00000000013; Tolerance_%: 5; Value1: Unknown; VDC_V: 100; Value2: 100V; TaMin_C: -55; TaMax_C: 125; SizeArea_mm2: 1.28; SizeAreaWB_mm2: 4.68; SizeX_mm: 1.6; SizeY_mm: 0.8; SizeZ_mm: 1; AEC Category: Q200
C284 C287-C291 C304-C308 C343 C345 = GRM21BR71A106KE51L: CAP, CERM, 10 µF, 10 V, +/- 10%, X7R, 0805; Manufacturer: MuRata; Polarized: N; CompType: Capacitor; Value: 10uF; U/M: EA; Cap_F: 0.00001; Tolerance_%: 10; ESR_ohm: 0.003; Value1: 0.003 ohm; Value2: 10V; TaMin_C: -55; TaMax_C: 125; Cap_Case: 0805; AEC Category: Q200
C318 C319 C321 = GRM188R71E105KA12D: CAP, CERM, 1 µF, 25 V, +/- 10%, X7R, 0603; Manufacturer: MuRata; Polarized: N; CompType: Capacitor; Value: 1uF; U/M: EA; Cap_F: 0.000001; Tolerance_%: 10; Value1: Unknown; VDC_V: 25; Value2: 25V; TaMin_C: -55; TaMax_C: 125; AEC Category: Q200
C320 = C0603C104J3RACTU: CAP, CERM, 0.1 µF, 25 V, +/- 5%, X7R, 0603; Manufacturer: Kemet; Polarized: N; CompType: Capacitor; Value: 0.1uF; U/M: EA; Cap_F: 0.0000001; Tolerance_%: 5; Value1: Unknown; VDC_V: 25; Value2: 25V; TaMin_C: -55; TaMax_C: 125; AEC Category: Q200
C322 C323 = C1608X5R1A226M080AC: CAP, CERM, 22 µF, 10 V, +/- 20%, X5R, 0603; Manufacturer: TDK; Polarized: N; CompType: Capacitor; Value: 22uF; U/M: EA; Cap_F: 0.000022; Tolerance_%: 20; ESR_ohm: 0.00371; Value1: 0.00371 ohm; VDC_V: 10; Value2: 10V; IRMS_A: 2.69936; TaMin_C: -55; TaMax_C: 85; SizeArea_mm2: 1.28; SizeAreaWB_mm2: 4.68; SizeX_mm: 1.6; SizeY_mm: 0.8; SizeZ_mm: 1; AEC Category: Q200
C335 = CGA3E2C0G1H103J080AA: CAP, CERM, 0.01 µF, 50 V, +/- 5%, C0G/NP0, AEC-Q200 Grade 1, 0603; Manufacturer: TDK; Polarized: N; CompType: Capacitor; Value: 0.01uF; U/M: EA; Cap_F: 0.00000001; Tolerance_%: 5; Value1: Unknown; VDC_V: 50; Value2: 50V; TaMin_C: -55; TaMax_C: 125; SizeArea_mm2: 1.28; SizeAreaWB_mm2: 4.68; SizeX_mm: 1.6; SizeY_mm: 0.8; SizeZ_mm: 1; AEC Category: Q200; AEC Qualified: Y
C449 C457-C459 = ZRB18AD71A106KE01L: CAP, CERM, 10 µF, 10 V, +/- 10%, X7T, 0603; Manufacturer: MuRata; Polarized: N; CompType: Capacitor; Value: 10uF; U/M: EA; Cap_F: 0.00001; Tolerance_%: 10; Value1: Unknown; Value2: 10V; TaMin_C: -55; TaMax_C: 125; Cap_Case: 0603; AEC Category: Q200
C452 = 0805YC224JAT2A: CAP, CERM, 0.22 µF, 16 V, +/- 5%, X7R, 0805; Manufacturer: AVX; Polarized: N; CompType: Capacitor; Value: 0.22uF; U/M: EA; Cap_F: 0.00000022; Tolerance_%: 5; ESR_ohm: 0.016; Value1: 0.016 ohm; VDC_V: 16; Value2: 16V; TaMin_C: -55; TaMax_C: 125; Cap_Case: 0805
C453 CR479 = GRM188R71E105KA12D: CAP, CERM, 1 µF, 25 V, +/- 10%, X7R, 0603; Manufacturer: MuRata; Polarized: N; CompType: Capacitor; Value: 1uF; U/M: EA; Cap_F: 0.000001; Tolerance_%: 10; Value1: Unknown; VDC_V: 25; Value2: 25V; TaMin_C: -55; TaMax_C: 125
C461 = C0603C100F5GAC7867: CAP, CERM, 10 pF, 50 V, +/- 1%, C0G/NP0, 0603; Manufacturer: Kemet; Polarized: N; CompType: Capacitor; Value: 10pF; U/M: EA; Cap_F: 0.00000000001; Tolerance_%: 1; Value1: Unknown; VDC_V: 50; Value2: 50V; TaMin_C: -55; TaMax_C: 125; AEC Category: Q200
CR481 = GRM21BR71A106KE51L: CAP, CERM, 10 µF, 10 V, +/- 10%, X7R, 0805; Manufacturer: MuRata; Polarized: N; CompType: Capacitor; Value: 10uF; U/M: EA; Cap_F: 0.00001; Tolerance_%: 10; ESR_ohm: 0.003; Value1: 0.003 ohm; Value2: 10V; TaMin_C: -55; TaMax_C: 125; Cap_Case: 0805
FDA1 = THS4551IRGTR: Low Power, Precision, 160MHz, Fully Differential Amplifier, RGT0016A; Alternate PartNumber: THS4551IRGTT; Manufacturer: Texas Instruments; SymbolCreator: Altium; SizeX_mm: 4; SizeZ_mm: 1; CompType: IC; U/M: EA
J14 J15 J18 J19 = 901-144-8RFX: SMA Straight Jack, Gold, 50 Ohm, TH; Manufacturer: Amphenol RF; SymbolCreator: X0208326
J37 J38 = TMM-103-01-G-S-SM: Header, 2mm, 3x1, Gold, SMT; Manufacturer: Samtec; SymbolCreator: a0799628; Pitch_mm: 2; Gender: Male; Shrouded: N; Row_Count: 1; Current_A: 3.2; Voltage_V: 500; Cert_CSA: Y
L6-L9 = MPZ2012S601A: Ferrite Bead, 600 ohm @ 100MHz, 2A, 0805; Manufacturer: TDK; Imax_A: 2; DCR_ohm: 0.1; Value1: 0.1 ohm; ZTyp@100MHz_Ohm: 600
OPAN_1 OPAP_1 = OPA827AIDR: Low-Noise, High-Precision, JFET-Input OPERATIONAL AMPLIFIER, D0008A; Manufacturer: Texas Instruments; SymbolCreator: a0411595/a0412235; CompType: IC; U/M: EA
OPAN_2 OPAP_2 = OPA827AIDR: Low-Noise, High-Precision, JFET-Input OPERATIONAL AMPLIFIER, D0008A; Manufacturer: Texas Instruments; SymbolCreator: a0411595/a0412235; SizeArea_mm2: 30.38; SizeAreaWB_mm2: 56.58; SizeX_mm: 4.9; SizeY_mm: 6.2; SizeZ_mm: 1.75; CompType: IC; U/M: EA
R3 R4 = ERJ-3RQFR22V: RES, 0.22 ohm, 1%, 0.1W, 0603; Manufacturer: Panasonic; CompType: Resistor; Value_Code: R220; Tolerance_%: 1; Power_W: 0.1; TempCo: 300 ppm/C; EIA_Code: E96; U/M: EA
R56 R211-R213 R223 R225 R226 R232-R235 R240 R248 R250 R252 R255 R259 R260 R262 R263 R284 R288 R453 R454 R457 REN0 REN1 RMFBN RMFBN2 RMFBP RMFBP2 RR457 = ERJ-2GE0R00X: RES, 0, 5%, 0.063 W, 0402; Manufacturer: Panasonic; CompType: Resistor; Value: 0; Value_Code: 0000; Tolerance_%: 5; Power_W: 0.063; Value2: 0.063W; VDC_V: 50; TempCo: 600 ppm/C; EIA_Code: E24; U/M: EA; AEC Category: Q200
R97 R98 R107 R108 R110 R214 = RG1608P-102-B-T5: RES, 1.00 k, 0.1%, 0.1 W, 0603; Manufacturer: Susumu Co Ltd; CompType: Resistor; Value: 1.00k; Res_ohm: 1000; Value_Code: 1k00; Tolerance_%: 0.1; Value2: 0.1W; VDC_V: 75; TempCo: 25 ppm/C; SizeArea_mm2: 1.28; SizeX_mm: 1.6; SizeY_mm: 0.8; SizeZ_mm: 1; EIA_Code: E192; U/M: EA; AEC Category: Q200
R99 = CRCW0603249RFKEA: RES, 249, 1%, 0.1 W, 0603; Manufacturer: Vishay-Dale; CompType: Resistor; Value: 249; Value_Code: 249R; Tolerance_%: 1; Power_W: 0.1; Value2: 0.1W; VDC_V: 75; TempCo: 100 ppm/C; SizeArea_mm2: 1.28; SizeX_mm: 1.6; SizeY_mm: 0.8; EIA_Code: E96; U/M: EA; AEC Category: Q200
R100 R101 R114 R116 RDN2 RDN4 RDP2 RDP4 = RT0603BRB071KL: RES, 1.00 k, 0.1%, 0.1 W, 0603; Manufacturer: Yageo America; CompType: Resistor; Value: 1.00k; Res_ohm: 1000; Value_Code: 1k00; Tolerance_%: 0.1; Value2: 0.1W; VDC_V: 75; TempCo: 10 ppm/C; SizeArea_mm2: 1.28; SizeX_mm: 1.6; SizeY_mm: 0.8; SizeZ_mm: 1; EIA_Code: E192; U/M: EA; AEC Category: Q200; AEC Qualified: N
R103 R104 R115 R117 = RT0603BRD0720RL: RES, 20.0, 0.1%, 0.1 W, 0603; Manufacturer: Yageo America; CompType: Resistor; Value: 20.0; Res_ohm: 20; Value_Code: 20R0; Tolerance_%: 0.1; Value2: 0.1W; VDC_V: 75; TempCo: 25 ppm/C; SizeArea_mm2: 1.28; SizeX_mm: 1.6; SizeY_mm: 0.8; SizeZ_mm: 1; EIA_Code: E192; U/M: EA; AEC Category: Q200
R112 R113 = RC0603FR-07124RL: RES, 124, 1%, 0.1 W, 0603; Manufacturer: Yageo America; CompType: Resistor; Value: 124; Value_Code: 124R; Tolerance_%: 1; Power_W: 0.1; Value2: 0.1W; VDC_V: 150; TempCo: 200 ppm/C; SizeArea_mm2: 1.28; SizeX_mm: 1.6; SizeY_mm: 0.8; EIA_Code: E96; U/M: EA; AEC Category: Q200
R215 = RG1608P-4990-B-T5: RES, 499, 0.1%, 0.1 W, 0603; Manufacturer: Susumu Co Ltd; CompType: Resistor; Value: 499; Value_Code: 499R; Tolerance_%: 0.1; Value2: 0.1W; VDC_V: 75; TempCo: 25 ppm/C; EIA_Code: E192; U/M: EA; AEC Category: Q200
R216 = RG1608P-203-B-T5: RES, 20.0 k, 0.1%, 0.1 W, 0603; Manufacturer: Susumu Co Ltd; CompType: Resistor; Value: 20.0k; Res_ohm: 20000; Value_Code: 20k0; Tolerance_%: 0.1; Value2: 0.1W; VDC_V: 75; TempCo: 25 ppm/C; EIA_Code: E192; U/M: EA; AEC Category: Q200
R217 R218 = RG1608P-4992-B-T5: RES, 49.9 k, 0.1%, 0.1 W, 0603; Manufacturer: Susumu Co Ltd; CompType: Resistor; Value: 49.9k; Res_ohm: 49900; Value_Code: 49k9; Tolerance_%: 0.1; Value2: 0.1W; VDC_V: 75; TempCo: 25 ppm/C; EIA_Code: E192; U/M: EA; AEC Category: Q200
R258 R261 = RG1608P-103-B-T5: RES, 10.0 k, 0.1%, 0.1 W, 0603; Manufacturer: Susumu Co Ltd; CompType: Resistor; Value: 10.0k; Res_ohm: 10000; Value_Code: 10k0; Tolerance_%: 0.1; Value2: 0.1W; VDC_V: 75; TempCo: 25 ppm/C; SizeArea_mm2: 1.28; SizeX_mm: 1.6; SizeY_mm: 0.8; SizeZ_mm: 1; EIA_Code: E192; U/M: EA; AEC Category: Q200
R268 R269 = CRCW06031R00FKEA: RES, 1.00, 1%, 0.1 W, 0603; Manufacturer: Vishay-Dale; CompType: Resistor; Value: 1.00; Res_ohm: 1; Value_Code: 1R00; Power_W: 0.1; Value2: 0.1W; VDC_V: 75; TempCo: 100 ppm/C; SizeArea_mm2: 1.28; SizeX_mm: 1.6; SizeY_mm: 0.8; EIA_Code: E96; U/M: EA; AEC Category: Q200
R485 R491 = RG1608P-102-B-T5: RES, 1.00 k, 0.1%, 0.1 W, 0603; Manufacturer: Susumu Co Ltd; CompType: Resistor; Value: 1.00k; Res_ohm: 1000; Value_Code: 1k00; Tolerance_%: 0.1; Value2: 0.1W; VDC_V: 75; TempCo: 25 ppm/C; EIA_Code: E192; U/M: EA
R486 = RG1608P-2491-B-T5: RES, 2.49 k, 0.1%, 0.1 W, 0603; Manufacturer: Susumu Co Ltd; CompType: Resistor; Value: 2.49k; Res_ohm: 2490; Value_Code: 2k49; Tolerance_%: 0.1; Value2: 0.1W; VDC_V: 75; TempCo: 25 ppm/C; EIA_Code: E192; U/M: EA
R488 = RG1608P-4991-B-T5: RES, 4.99 k, 0.1%, 0.1 W, 0603; Manufacturer: Susumu Co Ltd; CompType: Resistor; Value: 4.99k; Res_ohm: 4990; Value_Code: 4k99; Tolerance_%: 0.1; Value2: 0.1W; VDC_V: 75; TempCo: 25 ppm/C; EIA_Code: E192; U/M: EA
R489 = CRCW06034R75FKEA: RES, 4.75, 1%, 0.1 W, 0603; Manufacturer: Vishay-Dale; CompType: Resistor; Value: 4.75; Value_Code: 4R75; Tolerance_%: 1; Power_W: 0.1; Value2: 0.1W; VDC_V: 75; TempCo: 100 ppm/C; EIA_Code: E96; U/M: EA
R492 = RG1608P-4990-B-T5: RES, 499, 0.1%, 0.1 W, 0603; Manufacturer: Susumu Co Ltd; CompType: Resistor; Value: 499; Value_Code: 499R; Tolerance_%: 0.1; Value2: 0.1W; VDC_V: 75; TempCo: 25 ppm/C; EIA_Code: E192; U/M: EA
R494 = RG1608P-303-B-T5: RES, 30.0 k, 0.1%, 0.1 W, 0603; Manufacturer: Susumu Co Ltd; CompType: Resistor; Value: 30.0k; Res_ohm: 30000; Value_Code: 30k0; Tolerance_%: 0.1; Value2: 0.1W; VDC_V: 75; TempCo: 25 ppm/C; U/M: EA; AEC Category: Q200
RDN1 RDN3 RDP1 RDP3 = ERJ-3GEY0R00V: RES, 0, 5%, 0.1 W, 0603; Manufacturer: Panasonic; CompType: Resistor; Value: 0; Value_Code: 0000; Tolerance_%: 5; Power_W: 0.1; Value2: 0.1W; VDC_V: 50; TempCo: 600 ppm/C; EIA_Code: E24; U/M: EA; AEC Category: Q200
RR413 = ERJ-3RQFR22V: RES, 0.22, 1%, 0.1 W, 0603; Manufacturer: Panasonic; CompType: Resistor; Value: 0.22; Value_Code: R220; Tolerance_%: 1; Power_W: 0.1; Value2: 0.1W; TempCo: 300 ppm/C; EIA_Code: E96; U/M: EA
TP1 TP2 TP4 TP7 TP34 TP35 TPAGND = PogoPad: Pad for Pogo Pin Connector; SymbolCreator: codlsc
TP28-TP30 TPV4 = 5015: Test Point, Miniature, SMT; Manufacturer: Keystone; CompType: Test Point Loop
U1 U2 = OPA625IDBVR: High Bandwidth, High Precision, Low Noise and Distortion Amplifier with Ultra-Fast Transition time Low Power mode, DBV0006A; Alternate PartNumber: OPA625IDBVT; Manufacturer: Texas Instruments; SymbolCreator: Altium; SizeArea_mm2: 8.12; SizeAreaWB_mm2: 14.82; SizeX_mm: 2.8; SizeY_mm: 2.9; SizeZ_mm: 1.45; CompType: IC; U/M: EA
U3 = REF6041IDGKR: High-Precision Voltage Reference with Integrated High-Bandwidth Buffer, DGK0008A; Alternate PartNumber: REF6041IDGKT; Manufacturer: Texas Instruments; SymbolCreator: Altium; SizeArea_mm2: 15.655; SizeAreaWB_mm2: 35.955; SizeX_mm: 5.05; SizeY_mm: 3.1; SizeZ_mm: 1.1; CompType: IC; U/M: EA
U4 = OPA376AIDBVR: Precision, Low Noise, Low Iq Operational Amplifier, 2.2 to 5.5 V, -40 to 125 degC, 5-pin SOT23 (DBV0005A), Green (RoHS & no Sb/Br); Manufacturer: Texas Instruments; Alternate PartNumber: Equivalent; CMRR(Min)(dB): 76; IIB(Max)(pA): 10; Iq per channel(Max)(mA): 0.95; Number of Channels: 1; Offset Drift(Typ)(uV/C): 0.32; Slew Rate(Typ)(V/us): 2; Sub Family: Low Input Bias Current Amp (<=10pA), Low Noise Amp (<=10nV/rtHz), Low Offset Voltage Amplifier (<=500uV), Low Supply Voltage Amplifier (<=2.7V), Precision Amplifier; Total Supply Voltage(Max)(+5V is 5, +/-5V is 10): 5.5; Total Supply Voltage(Min)(+5V is 5, +/-5V is 10): 2.2; Vio (25C)(Max)(mV): 0.025; Vn at 1kHz(Typ)(nV/rtHz): 7.5
U18 U31 = SN74AUP1G80DCKR: LOW-POWER SINGLE POSITIVE-EDGE-TRIGGERED D-TYPE FLIP-FLOP, DCK0005A; Alternate PartNumber: SN74AUP1G80DCKT; Manufacturer: Texas Instruments; SymbolCreator: Altium; SizeArea_mm2: 4.2; SizeAreaWB_mm2: 9.3; SizeX_mm: 2.1; SizeY_mm: 2; SizeZ_mm: 1.1; CompType: IC; U/M: EA
U19 U32 = SN74AHC1G04DBVR: SINGLE SCHMITT-TRIGGER INVERTER GATE, DBV0005A; Alternate PartNumber: SN74AHC1G04DBVT; Manufacturer: Texas Instruments; SymbolCreator: a0411947; CompType: IC; U/M: EA
U414 = OPA378AIDBVT: Low-Noise, 900 kHz, RRIO, Precision Operational Amplifier, Zerø-Drift Series, 2.2 to 5.5 V, -40 to 125 degC, 5-pin SOT23 (DBV0005A), Green (RoHS & no Sb/Br); Manufacturer: Texas Instruments; Alternate PartNumber: Equivalent; CMRR(Min)(dB): 100; IIB(Max)(pA): 550; Iq per channel(Max)(mA): 0.15; Number of Channels: 1; Offset Drift(Typ)(uV/C): 0.1; Slew Rate(Typ)(V/us): 0.4; Sub Family: Low Input Bias Current Amp (<=10pA), Low Offset Voltage Amplifier (<=500uV), Low Power Amp (<=500uA), Low Supply Voltage Amplifier (<=2.7V), Precision Amplifier, Zero Drift Precision Amplifier; Total Supply Voltage(Max)(+5V is 5, +/-5V is 10): 5.5; Total Supply Voltage(Min)(+5V is 5, +/-5V is 10): 2.2; Vio (25C)(Max)(mV): 0.05; Vn at 1kHz(Typ)(nV/rtHz): 20
U415 = OPA625IDBVR: High-Bandwidth, High-Precision, Low THD+N, 16-Bit and 18-Bit Analog-to-Digital Converter (ADC) Drivers, DBV0006A; Alternate PartNumber: OPA625IDBVT; Manufacturer: Texas Instruments; SymbolCreator: Altium; CompType: IC; U/M: EA
U422 = REF5040AIDGKT: Low Noise, Very Low Drift, Precision Voltage Reference, -40 to 125 degC, 8-pin MSOP (DGK), Green (RoHS & no Sb/Br); Manufacturer: Texas Instruments; Alternate PartNumber: Equivalent; Initial Accuracy @ 25/deg C(%): 0.05; Iout/Iz(Max)(mA): 10; Iq(Max)(uA): 1000; Rating: Catalog; SubFamily: Series Voltage Reference; Temp Coeff(Max)(ppm/ degree C): 3; VI(Max)(V): 18; VI(Min)(V): 4.296; VO(V): 4.096
UADS1 UADS2 = ADS8900BRGER: 20-Bit, High-Speed SAR ADCs With Integrated Reference Buffer, Integrated LDO, and multiSPI Digital Interface, RGE0024H (VQFN-24); Alternate PartNumber: ADS8900BRGET; Manufacturer: Texas Instruments; SymbolCreator: Altium; CompType: IC; U/M: EA; SizeArea_mm2: 16; SizeAreaWB_mm2: 25; SizeX_mm: 4; SizeZ_mm: 1

## Sheet OPA625 ADC Driver_Clock.SchDoc
size 431 x 279 mm; Date: Not shown in title block; ApprovedBy: Not shown in title block; CheckedBy: Not shown in title block; Author: Not shown in title block; CompanyName: Not shown in title block; Engineer: Not shown in title block; Organization: Not shown in title block; Address1: Not shown in title block; Address2: Not shown in title block; Address3: Not shown in title block; Address4: Not shown in title block; DocumentNumber: 7; Revision: Use project parameter SCH_Rev; SheetNumber: 7; SheetTotal: 8; PageSetup: Record=PageOptions¦CenterHorizontal=True¦CenterVertical=True¦PrintScale=0.96¦XCorrection=1.00¦YCorrection=1.00¦PrintKind=0¦BorderSize=5000000¦LeftOffset=0¦BottomOffset=0¦Orientation=2¦PaperLength=1000¦PaperWidth=1000¦Scale=100¦PaperSource=15¦PrintQuality=-3¦MediaType=1¦DitherType=10¦PrintScaleMode=1¦PaperKind=Tabloid (11 x 17")¦PaperIndex=17

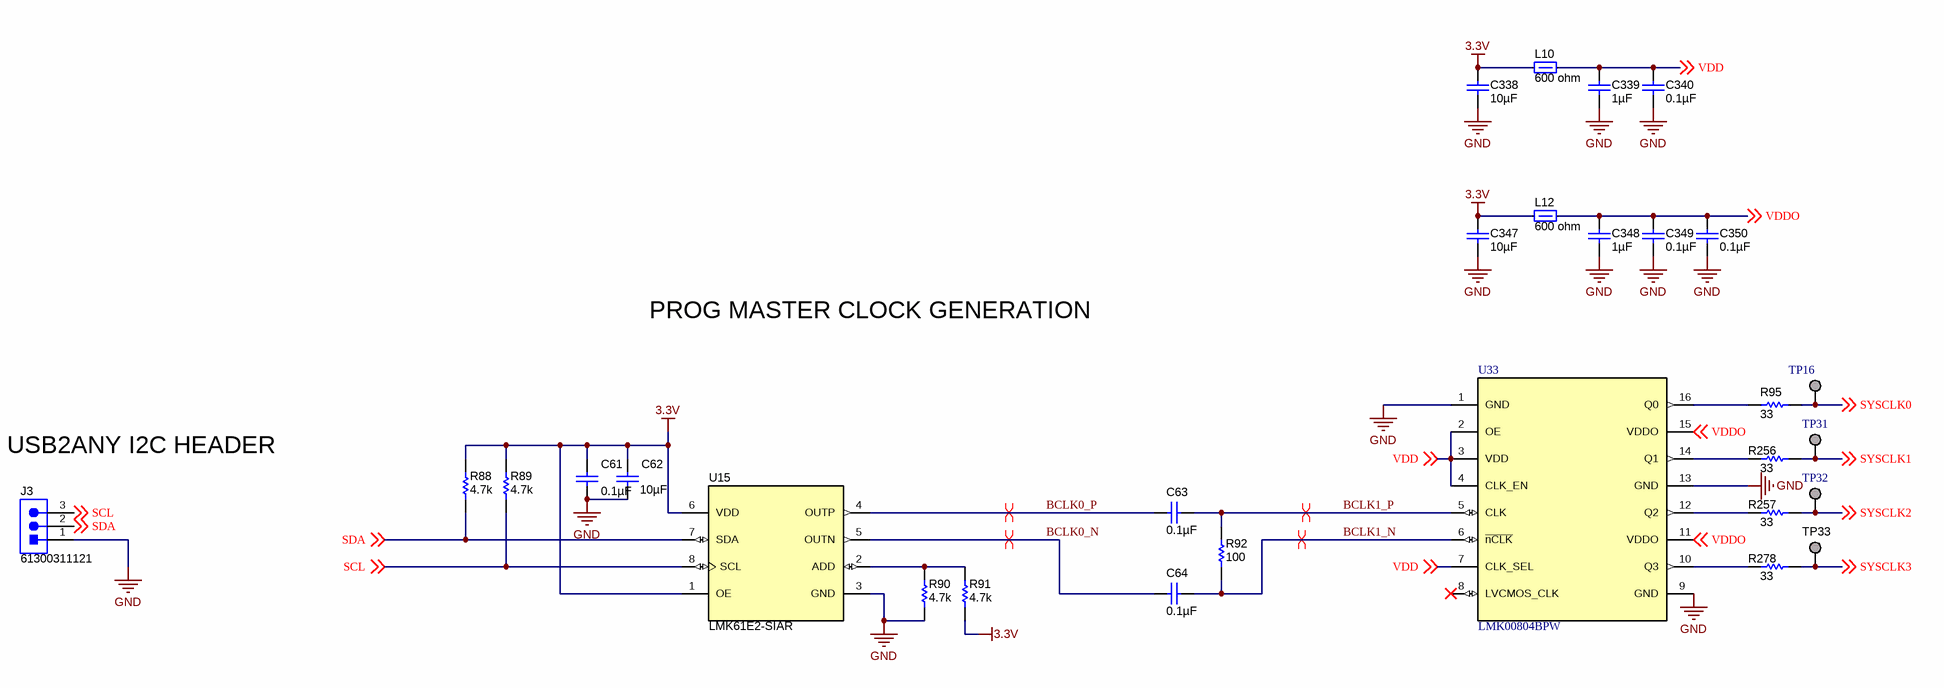
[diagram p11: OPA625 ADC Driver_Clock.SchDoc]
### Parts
C61  ValueDisplayed: 0.1µF  [0603]  (hidden comment: C0603C104J3RACTU)
C62  ValueDisplayed: 10µF  [0603_120]  (hidden comment: ZRB18AD71A106KE01L)
C63  ValueDisplayed: 0.1µF  [0402]  (hidden comment: GRM155R61E104KA87D)
C64  ValueDisplayed: 0.1µF  [0402]  (hidden comment: GRM155R61E104KA87D)
C338  ValueDisplayed: 10µF  [0805_HV]  (hidden comment: GRM21BR71A106KE51L)
C339  ValueDisplayed: 1µF  [0603]  (hidden comment: GRM188R71E105KA12D)
C340  ValueDisplayed: 0.1µF  [0402]  (hidden comment: GRM155R71C104KA88D)
C347  ValueDisplayed: 10µF  [0805_HV]  (hidden comment: GRM21BR71A106KE51L)
C348  ValueDisplayed: 1µF  [0603]  (hidden comment: GRM188R71E105KA12D)
C349  ValueDisplayed: 0.1µF  [0402]  (hidden comment: GRM155R71C104KA88D)
C350  ValueDisplayed: 0.1µF  [0402]  (hidden comment: GRM155R71C104KA88D)
J3  61300311121  [WURTH_61300311121]
L10  value 600 ohm  [0805_HV]  (hidden comment: MPZ2012S601A)
L12  value 600 ohm  [0805_HV]  (hidden comment: MPZ2012S601A)
R88  ValueDisplayed: 4.7k  [0402]  (hidden comment: CRCW04024K70JNED)
R89  ValueDisplayed: 4.7k  [0402]  (hidden comment: CRCW04024K70JNED)
R90  ValueDisplayed: 4.7k  [0402]  (hidden comment: CRCW04024K70JNED)
R91  ValueDisplayed: 4.7k  [0402]  (hidden comment: CRCW04024K70JNED)
R92  ValueDisplayed: 100  [0402]  (hidden comment: CRCW0402100RJNED)
R95  ValueDisplayed: 33  [0402]  (hidden comment: CRCW040233R0JNED)
R256  ValueDisplayed: 33  [0402]  (hidden comment: CRCW040233R0JNED)
R257  ValueDisplayed: 33  [0402]  (hidden comment: CRCW040233R0JNED)
R278  ValueDisplayed: 33  [0402]  (hidden comment: CRCW040233R0JNED)
TP16  Pogo Pad  [PogoPad]  (value not drawn)  (no BOM)
TP31  Pogo Pad  [PogoPad]  (value not drawn)  (no BOM)
TP32  Pogo Pad  [PogoPad]  (value not drawn)  (no BOM)
TP33  Pogo Pad  [PogoPad]  (value not drawn)  (no BOM)
U15  LMK61E2-SIAR  [SIA0008B]
U33  LMK00804BPW  [PW0016A_N]

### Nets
3.3V: C61.1 C62.1 C338.1 C347.1 L10.2 L12.2 R88.2 R89.2 R91.1 U15.1(OE) U15.6(VDD)
GND: C61.2 C62.2 C338.2 C339.2 C340.2 C347.2 C348.2 C349.2 C350.2 J3.1 R90.1 U15.3(GND) U33.1(GND) U33.9(GND) U33.13(GND)
BCLK0_N: C64.1 U15.5(OUTN)
BCLK0_P: C63.1 U15.4(OUTP)
BCLK1_N: C64.2 R92.1 U33.6(~{nCLK})
BCLK1_P: C63.2 R92.2 U33.5(CLK)
SCL: J3.3 R89.1 U15.8(SCL) ; off-sheet SCL
SDA: J3.2 R88.1 U15.7(SDA) ; off-sheet SDA
SYSCLK0: R95.2 TP16.1 ; off-sheet SYSCLK0
SYSCLK1: R256.2 TP31.1 ; off-sheet SYSCLK1
SYSCLK2: R257.2 TP32.1 ; off-sheet SYSCLK2
SYSCLK3: R278.2 TP33.1 ; off-sheet SYSCLK3
VDD: C339.1 C340.1 L10.1 U33.2(OE) U33.3(VDD) U33.4(CLK_EN) U33.7(CLK_SEL) ; off-sheet VDD
VDDO: C348.1 C349.1 C350.1 L12.1 U33.11(VDDO) U33.15(VDDO) ; off-sheet VDDO
NetR90_2: R90.2 R91.2 U15.2(ADD)
NetR95_1: R95.1 U33.16(Q0)
NetR256_1: R256.1 U33.14(Q1)
NetR257_1: R257.1 U33.12(Q2)
NetR278_1: R278.1 U33.10(Q3)

Not connected (* = marked no-connect by the designer): U33 8(LVCMOS_CLK)*

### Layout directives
differential pair: BCLK0_N, BCLK0_P, BCLK1_N, BCLK1_P

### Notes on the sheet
- PROG MASTER CLOCK GENERATION
- USB2ANY I2C HEADER

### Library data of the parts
C61 = C0603C104J3RACTU: as C84 on sheet OPA625 ADC Driver_OPA625 ADC Driver REV1.0
C62 = ZRB18AD71A106KE01L: as C449 on sheet OPA625 ADC Driver_OPA625 ADC Driver REV1.0
C63 C64 = GRM155R61E104KA87D: CAP, CERM, 0.1 µF, 25 V, +/- 10%, X5R, 0402; Manufacturer: MuRata; Polarized: N; CompType: Capacitor; Value: 0.1uF; U/M: EA; Cap_F: 0.0000001; Tolerance_%: 10; Value1: Unknown; VDC_V: 25; Value2: 25V; TaMin_C: -55; TaMax_C: 85; AEC Category: Q200
C338 C347 = GRM21BR71A106KE51L: as C284 on sheet OPA625 ADC Driver_OPA625 ADC Driver REV1.0
C339 C348 = GRM188R71E105KA12D: as C318 on sheet OPA625 ADC Driver_OPA625 ADC Driver REV1.0
C340 C349 C350 = GRM155R71C104KA88D: as C94 on sheet OPA625 ADC Driver_OPA625 ADC Driver REV1.0
J3 = 61300311121: Header, 2.54 mm, 3x1, Gold, TH; Manufacturer: Wurth Elektronik eiSos; SymbolCreator: a0799628; U/M: EA
L10 L12 = MPZ2012S601A: as L6-L9 on sheet OPA625 ADC Driver_OPA625 ADC Driver REV1.0
R88-R91 = CRCW04024K70JNED: RES, 4.7 k, 5%, 0.063 W, 0402; Manufacturer: Vishay-Dale; CompType: Resistor; Value: 4.7k; Res_ohm: 4700; Value_Code: 4k70; Tolerance_%: 5; Power_W: 0.063; Value2: 0.063W; VDC_V: 50; TempCo: 200 ppm/C; EIA_Code: E24; U/M: EA; AEC Category: Q200
R92 = CRCW0402100RJNED: RES, 100, 5%, 0.063 W, 0402; Manufacturer: Vishay-Dale; CompType: Resistor; Value: 100; Value_Code: 100R; Tolerance_%: 5; Power_W: 0.063; Value2: 0.063W; VDC_V: 50; TempCo: 200 ppm/C; EIA_Code: E24; U/M: EA; AEC Category: Q200
R95 R256 R257 R278 = CRCW040233R0JNED: RES, 33, 5%, 0.063 W, 0402; Manufacturer: Vishay-Dale; CompType: Resistor; Value: 33; Value_Code: 33R0; Tolerance_%: 5; Power_W: 0.063; Value2: 0.063W; VDC_V: 50; TempCo: 200 ppm/C; EIA_Code: E24; U/M: EA; AEC Category: Q200
TP16 TP31-TP33 = PogoPad: as TP1 on sheet OPA625 ADC Driver_OPA625 ADC Driver REV1.0
U15 = LMK61E2-SIAR: Ultra-Low Jitter Programmable Oscillator with Internal EEPROM, SIA0008B; Alternate PartNumber: LMK61E2-SIAT; Manufacturer: Texas Instruments; SymbolCreator: Altium; CompType: IC; U/M: EA
U33 = LMK00804BPW: Low Skew, 1-to-4 Multiplexed Differential/LVCMOS-to-LVCMOS/TTL Fanout Buffer, PW0016A; Manufacturer: Texas Instruments; SymbolCreator: a0411947; SizeArea_mm2: 32; SizeAreaWB_mm2: 58.8; SizeX_mm: 6.4; SizeY_mm: 5; SizeZ_mm: 1.2; CompType: IC; U/M: EA

## Sheet OPA625 ADC Driver_Hardware.SchDoc
size 431 x 279 mm; Date: Not shown in title block; ApprovedBy: Not shown in title block; CheckedBy: Not shown in title block; Author: Not shown in title block; CompanyName: Not shown in title block; Engineer: Not shown in title block; Organization: Not shown in title block; Address1: Not shown in title block; Address2: Not shown in title block; Address3: Not shown in title block; Address4: Not shown in title block; DocumentNumber: 8; Revision: Use project parameter SCH_Rev; SheetNumber: 8; SheetTotal: 8; PageSetup: Record=PageOptions¦CenterHorizontal=True¦CenterVertical=True¦PrintScale=1.00¦XCorrection=1.00¦YCorrection=1.00¦PrintKind=0¦BorderSize=5000000¦LeftOffset=0¦BottomOffset=0¦Orientation=2¦PaperLength=1000¦PaperWidth=1000¦Scale=100¦PaperSource=15¦PrintQuality=600¦MediaType=1¦DitherType=10¦PaperKind=Letter¦PrintScaleMode=1

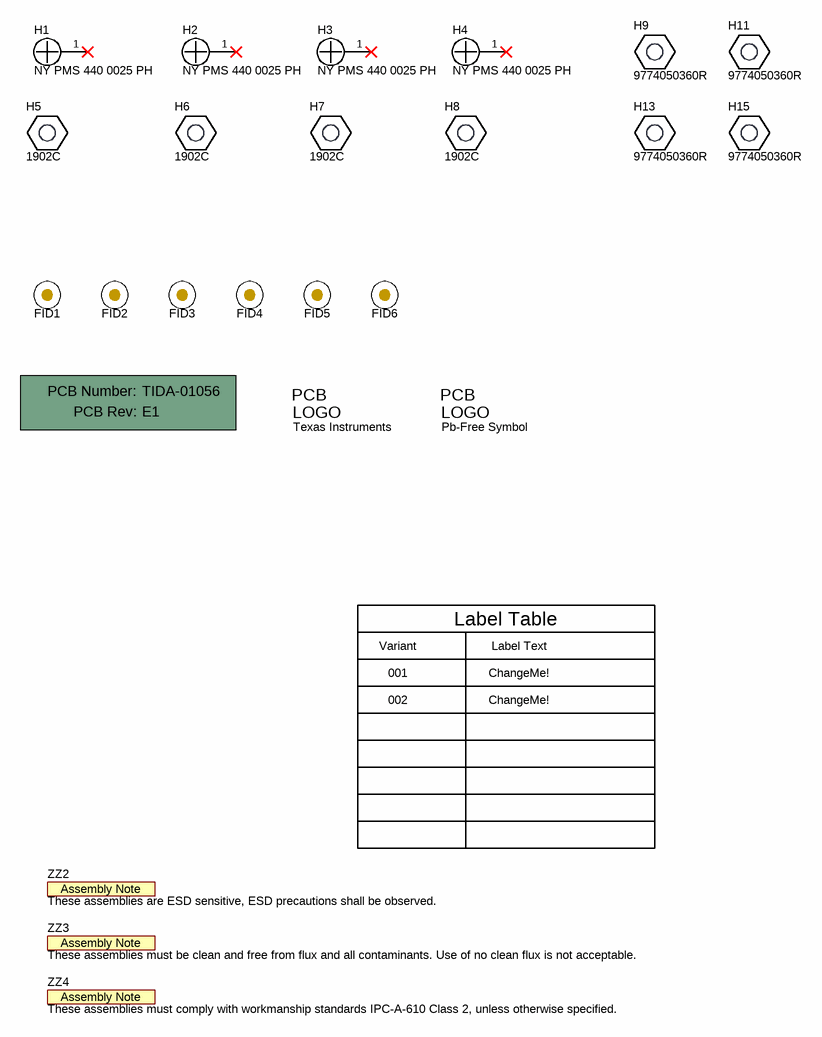
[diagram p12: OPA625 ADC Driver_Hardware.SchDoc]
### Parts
!PCB  Printed Circuit Board  (value not drawn)  (mechanical)
FID1  Fiducial  [Fiducial10-20]  (value not drawn)
FID2  Fiducial  [Fiducial10-20]  (value not drawn)
FID3  Fiducial  [Fiducial10-20]  (value not drawn)
FID4  Fiducial  [Fiducial10-20]  (value not drawn)
FID5  Fiducial  [Fiducial10-20]  (value not drawn)
FID6  Fiducial  [Fiducial10-20]  (value not drawn)
H1  NY PMS 440 0025 PH  [NY PMS 440 0025 PH]
H2  NY PMS 440 0025 PH  [NY PMS 440 0025 PH]
H3  NY PMS 440 0025 PH  [NY PMS 440 0025 PH]
H4  NY PMS 440 0025 PH  [NY PMS 440 0025 PH]
H5  1902C  [Keystone_1902C]
H6  1902C  [Keystone_1902C]
H7  1902C  [Keystone_1902C]
H8  1902C  [Keystone_1902C]
H9  9774050360R  [Wurth_WA-SMSI]
H11  9774050360R  [Wurth_WA-SMSI]
H13  9774050360R  [Wurth_WA-SMSI]
H15  9774050360R  [Wurth_WA-SMSI]
Logo1  Texas Instruments  [TI_Stacked_Overlay_Small]  (no BOM)
Logo2  Pb-Free Symbol  [Pb-Free_Overlay_Small]  (no BOM)
ZZ2  These assemblies are ESD sensitive, ESD precautions shall be observed.  [AssemblyNote]  (no BOM)
ZZ3  These assemblies must be clean and free from flux and all contaminants. Use of no clean flux is not acceptable.  [AssemblyNote]  (no BOM)
ZZ4  These assemblies must comply with workmanship standards IPC-A-610 Class 2, unless otherwise specified.  [AssemblyNote]  (no BOM)

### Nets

Not connected (* = marked no-connect by the designer): H1 1*; H2 1*; H3 1*; H4 1*

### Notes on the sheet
- Variant
- Label Table
- Label Text
- 001
- 002
- ChangeMe!

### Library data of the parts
!PCB = PCB: Manufacturer: Any; PartNumber: TIDA-01056; SymbolCreator: a0412235
FID1-FID6 = Fiducial: Fiducial mark.  There is nothing to buy or mount.; SymbolCreator: codlsc
H1-H4 = NY PMS 440 0025 PH: Machine Screw, Round, #4-40 x 1/4, Nylon, Philips panhead; Manufacturer: B&F Fastener Supply; CompType: Hardware; SymbolCreator: codlsc; U/M: EA
H5-H8 = 1902C: Standoff, Hex, 0.5"L #4-40 Nylon; Manufacturer: Keystone; CompType: Hardware
H9 H11 H13 H15 = 9774050360R: ROUND STANDOFF M3 STEEL 5MM; Manufacturer: Wurth Elektronik; SymbolCreator: a0412235
Logo1 = TI_Logo: Texas Instrument Corporate Signature; SymbolCreator: codlsc
Logo2 = Pb-Free: SymbolCreator: a0412235
ZZ2-ZZ4 = AssemblyNote: SymbolCreator: codlsc

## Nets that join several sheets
3.3V: OPA625 ADC Driver_Power_1051 (8 pins), OPA625 ADC Driver_OPA625 ADC Driver REV1.0 (14 pins), OPA625 ADC Driver_Clock (11 pins)
5V: OPA625 ADC Driver_Power_1051 (9 pins), OPA625 ADC Driver_OPA625 ADC Driver REV1.0 (29 pins)
+18V: OPA625 ADC Driver_Power_1051 (7 pins), OPA625 ADC Driver_OPA625 ADC Driver REV1.0 (8 pins)
+24VDC: OPA625 ADC Driver_Power_1051 (6 pins), OPA625 ADC Driver_Power_1050 (JMTI_-18V.2 JZI_3.3V.2 JZI_5V.2 JZI_18V.2)
-18V: OPA625 ADC Driver_Power_1051 (6 pins), OPA625 ADC Driver_OPA625 ADC Driver REV1.0 (8 pins)
AGND: OPA625 ADC Driver_Power_1051 (6 pins), OPA625 ADC Driver_OPA625 ADC Driver REV1.0 (97 pins)
GND: OPA625 ADC Driver_Power_1051 (163 pins), OPA625 ADC Driver_Power_1050 (31 pins), OPA625 ADC Driver_Connectors (34 pins), OPA625 ADC Driver_OPA625 ADC Driver REV1.0 (12 pins), OPA625 ADC Driver_Clock (15 pins)
VEE: OPA625 ADC Driver_Power_1051 (J39.2), OPA625 ADC Driver_OPA625 ADC Driver REV1.0 (5 pins)
1050_3.3V: OPA625 ADC Driver_Power_1051 (JTI_3.3V.3), OPA625 ADC Driver_Power_1050 (5 pins)
1050_5V: OPA625 ADC Driver_Power_1051 (JTI_5V.3), OPA625 ADC Driver_Power_1050 (Cff2.1 Cout4.1 Rfbt2.2 U23.7)
1050_18V: OPA625 ADC Driver_Power_1051 (JTI_18V.3), OPA625 ADC Driver_Power_1050 (6 pins)
1050_-18V: OPA625 ADC Driver_Power_1051 (JTI_-18V.1), OPA625 ADC Driver_Power_1050 (10 pins)
CONVST: OPA625 ADC Driver_Connectors (R67.1 R78.1), OPA625 ADC Driver_OPA625 ADC Driver REV1.0 (6 pins)
CSn: OPA625 ADC Driver_Connectors (R68.1 R79.1), OPA625 ADC Driver_OPA625 ADC Driver REV1.0 (UADS1.24 UADS2.24)
RVS_DIF: OPA625 ADC Driver_Connectors (R71.1), OPA625 ADC Driver_OPA625 ADC Driver REV1.0 (UADS1.21)
RVS_SE: OPA625 ADC Driver_Connectors (R82.1), OPA625 ADC Driver_OPA625 ADC Driver REV1.0 (UADS2.21)
SCLK_Phi: OPA625 ADC Driver_Connectors (R69.1 R80.1), OPA625 ADC Driver_OPA625 ADC Driver REV1.0 (UADS1.23 UADS2.23)
SDI: OPA625 ADC Driver_Connectors (R66.1 R77.1), OPA625 ADC Driver_OPA625 ADC Driver REV1.0 (UADS1.22 UADS2.22)
SDO0_DIF: OPA625 ADC Driver_Connectors (R72.1), OPA625 ADC Driver_OPA625 ADC Driver REV1.0 (R235.2)
SDO0_SE: OPA625 ADC Driver_Connectors (R83.1), OPA625 ADC Driver_OPA625 ADC Driver REV1.0 (R226.2)
SDO1_DIF: OPA625 ADC Driver_Connectors (R73.1), OPA625 ADC Driver_OPA625 ADC Driver REV1.0 (R234.2)
SDO1_SE: OPA625 ADC Driver_Connectors (R84.1), OPA625 ADC Driver_OPA625 ADC Driver REV1.0 (R225.2)
SDO2_DIF: OPA625 ADC Driver_Connectors (R74.1), OPA625 ADC Driver_OPA625 ADC Driver REV1.0 (R233.2)
SDO2_SE: OPA625 ADC Driver_Connectors (R85.1), OPA625 ADC Driver_OPA625 ADC Driver REV1.0 (R240.2)
SDO3_DIF: OPA625 ADC Driver_Connectors (R75.1), OPA625 ADC Driver_OPA625 ADC Driver REV1.0 (R232.2)
SDO3_SE: OPA625 ADC Driver_Connectors (R86.1), OPA625 ADC Driver_OPA625 ADC Driver REV1.0 (R223.2)
SRESETn: OPA625 ADC Driver_Connectors (R65.1 R76.1), OPA625 ADC Driver_OPA625 ADC Driver REV1.0 (UADS1.2 UADS2.2)
SYSCLK0: OPA625 ADC Driver_OPA625 ADC Driver REV1.0 (U18.2 U31.2), OPA625 ADC Driver_Clock (R95.2 TP16.1)
SYSCLK1: OPA625 ADC Driver_Connectors (R70.1 R81.1), OPA625 ADC Driver_Clock (R256.2 TP31.1)

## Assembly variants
001: not fitted C89 C90 C316 C317 C335 C409 CMFB FID1 FID2 FID3 FID4 FID5 FID6 R11 R12 R15 R17 R18 R20 R24 R26 R27 R29 R30 R31 R33 R34 R90 R255 R260 R263 R453 R457 REN0 REN1 RMFBN RMFBP RR457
